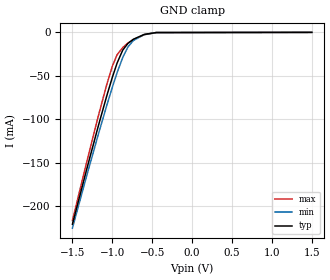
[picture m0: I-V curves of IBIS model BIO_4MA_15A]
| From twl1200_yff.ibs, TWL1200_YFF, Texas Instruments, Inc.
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[Model]   BIO_4MA_15A
Model_type  Input
Vinl=0.525
Vinh=0.975
| variable   typ   min   max
C_comp   2.92pF   2.50pF   3.51pF
[Temperature Range]   40   100   -40
| Ambient temperature   25   85   -40
[Voltage range]   1.5   1.4   1.6
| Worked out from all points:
|   GND clamp passes 1 mA (typ) near -0.53 V on its own axis
[GND Clamp]
| BIO_4MA_15A
|   Voltage   I(typ)   I(min)   I(max)
-1.5V     -220.4mA   -224.9mA   -216.2mA
-1.315V   -155.2mA   -162.8mA   -146.8mA
-1.175V   -107.4mA   -117.1mA   -96.01mA
-1.07V    -73.08mA   -84.08mA   -60.07mA
-1V       -51.72mA   -63.14mA   -38.92mA
-940mV    -35.29mA   -46.32mA   -25.69mA
-870mV    -20.5mA    -28.99mA   -17.51mA
-805mV    -12.74mA   -16.84mA   -12.3mA
-735mV    -7.856mA   -9.302mA   -8.241mA
-600mV    -2.372mA   -2.551mA   -2.677mA
-450mV    -245.3uA   -217.8uA   -153.4uA
1.5V      403.3pA    13.93nA    48.42pA
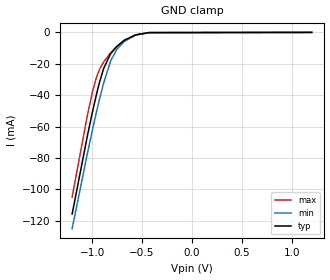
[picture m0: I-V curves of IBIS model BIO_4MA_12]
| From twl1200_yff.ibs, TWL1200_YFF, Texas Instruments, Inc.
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[Model]   BIO_4MA_12
Model_type  Input
Vinl=0.24
Vinh=0.96
| variable   typ   min   max
C_comp   2.96pF   2.58pF   3.55pF
[Temperature Range]   40   100   -40
| Ambient temperature   25   85   -40
[Voltage range]   1.2   1.1   1.3
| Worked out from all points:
|   GND clamp passes 1 mA (typ) near -0.53 V on its own axis
[GND Clamp]
| BIO_4MA_12
|   Voltage   I(typ)   I(min)   I(max)
-1.2V     -115.8mA   -125.1mA   -104.9mA
-1.045V   -65.27mA   -76.48mA   -52.1mA
-995mV    -50.27mA   -61.69mA   -37.59mA
-955mV    -39.16mA   -50.39mA   -28.36mA
-925mV    -31.62mA   -42.35mA   -23.44mA
-885mV    -23.11mA   -32.41mA   -18.91mA
-815mV    -13.64mA   -18.38mA   -13.02mA
-755mV    -9.083mA   -10.95mA   -9.266mA
-680mV    -5.018mA   -5.906mA   -5.701mA
-565mV    -1.615mA   -1.577mA   -1.685mA
-430mV    -157.4uA   -145uA     -87.99uA
1.2V      356.6pA    13.86nA    37.75pA
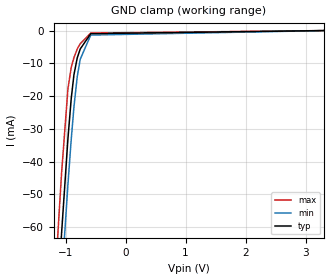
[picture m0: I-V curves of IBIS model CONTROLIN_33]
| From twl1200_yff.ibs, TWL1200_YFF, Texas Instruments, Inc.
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[Model]   CONTROLIN_33
Model_type  Input
Vinl=1.155
Vinh=2.145
| variable   typ   min   max
C_comp   1.78pF   1.41pF   2.49pF
[Temperature Range]   40   100   -40
| Ambient temperature   25   85   -40
[Voltage range]   3.3   3   3.6
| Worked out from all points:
|   GND clamp passes 1 mA (typ) near -0.58 V on its own axis
[GND Clamp]
| CONTROLIN_33
|   Voltage   I(typ)   I(min)   I(max)
-3.3V     -813.2mA   -810.9mA   -816.4mA
-1.18V    -96.35mA   -110.5mA   -78.5mA
-1.16V    -90.16mA   -104.4mA   -72.15mA
-1.11V    -74.91mA   -89.37mA   -56.61mA
-1.065V   -61.57mA   -76.14mA   -43.25mA
-960mV    -32.92mA   -46.91mA   -17.75mA
-905mV    -20.71mA   -33.14mA   -11.18mA
-860mV    -13.47mA   -23.31mA   -8.251mA
-805mV    -8.346mA   -14.02mA   -5.606mA
-755mV    -5.604mA   -8.734mA   -3.984mA
-580mV    -942uA     -1.365mA   -758.1uA
3.3V      193.8pA    963.2pA    46.32pA
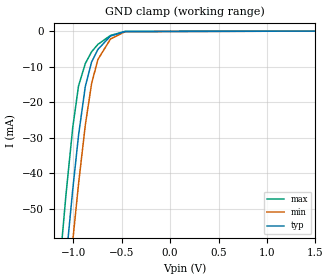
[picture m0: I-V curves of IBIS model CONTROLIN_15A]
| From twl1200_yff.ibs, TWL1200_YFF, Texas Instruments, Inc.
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[Model]   CONTROLIN_15A
Model_type  Input
Vinl=0.525
Vinh=0.975
| variable   typ   min   max
C_comp   1.95pF   1.64pF   2.47pF
[Temperature Range]   40   100   -40
| Ambient temperature   25   85   -40
[Voltage range]   1.5   1.4   1.6
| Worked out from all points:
|   GND clamp passes 1 mA (typ) near -0.58 V on its own axis
[GND Clamp]
| CONTROLIN_15A
|   Voltage   I(typ)   I(min)   I(max)
-1.5V     -199.5mA   -211.2mA   -185mA
-1.32V    -140.7mA   -153.9mA   -124.3mA
-1.18V    -96.35mA   -110.5mA   -78.5mA
-1.075V   -64.5mA    -79.05mA   -46.15mA
-1.005V   -44.62mA   -59.08mA   -27.16mA
-945mV    -29.31mA   -43.01mA   -15.42mA
-875mV    -15.55mA   -26.4mA    -9.12mA
-810mV    -8.688mA   -14.72mA   -5.81mA
-745mV    -5.153mA   -7.982mA   -3.732mA
-615mV    -1.388mA   -2.223mA   -1.219mA
-465mV    -156.2uA   -176.2uA   -62.84uA
1.5V      116.5pA    788.9pA    20.38pA
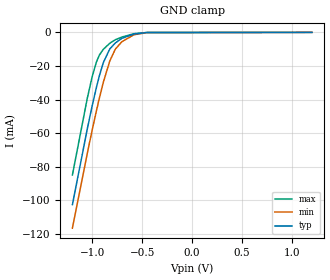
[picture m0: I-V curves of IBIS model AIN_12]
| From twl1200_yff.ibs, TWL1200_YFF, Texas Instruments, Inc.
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[Model]   AIN_12
Model_type  Input
Vinl=0.24
Vinh=0.96
| variable   typ   min   max
C_comp   2.13pF   1.79pF   2.63pF
[Temperature Range]   40   100   -40
| Ambient temperature   25   85   -40
[Voltage range]   1.2   1.1   1.3
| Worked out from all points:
|   GND clamp passes 1 mA (typ) near -0.59 V on its own axis
[GND Clamp]
| AIN_12
|   Voltage   I(typ)   I(min)   I(max)
-1.2V     -102.6mA   -116.6mA   -84.91mA
-1.05V    -57.23mA   -71.81mA   -38.99mA
-1V       -43.27mA   -57.7mA    -25.97mA
-960mV    -32.92mA   -46.91mA   -17.75mA
-930mV    -25.89mA   -39.21mA   -13.53mA
-890mV    -17.97mA   -29.69mA   -10.08mA
-825mV    -9.835mA   -16.99mA   -6.47mA
-770mV    -6.329mA   -10.03mA   -4.398mA
-705mV    -3.573mA   -5.62mA    -2.835mA
-585mV    -997.9uA   -1.471mA   -816.9uA
-455mV    -126.6uA   -144.1uA   -47.34uA
1.2V      105.6pA    761pA      16.3pA
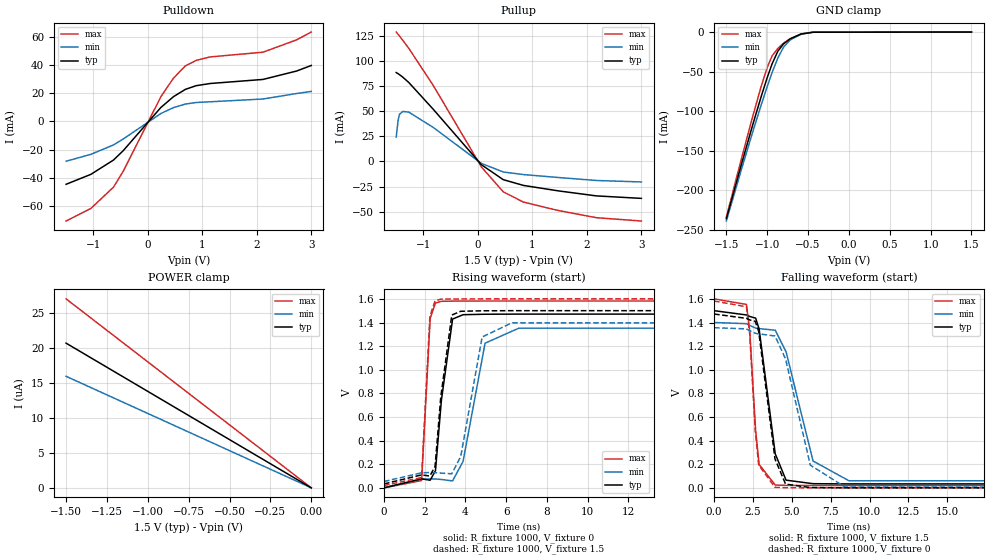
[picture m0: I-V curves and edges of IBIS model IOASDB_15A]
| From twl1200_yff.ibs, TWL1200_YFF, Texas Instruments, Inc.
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[Model]   IOASDB_15A
Model_type  I/O
Vinl=0.525
Vinh=0.975
Enable   Active-Low
Vref =   1.5
Rref =   1M
Cref =   15p
Vmeas =   0.75
| variable   typ   min   max
C_comp   4.28pF   3.66pF   5.02pF
| C_pullup   6.70pF   4.20pF   7.93pF
| C_pulldown   5.84pF   4.76pF   6.78pF
| C_tri-state   4.28pF   3.66pF   5.02pF
[Temperature Range]   40   100   -40
| Ambient temperature   25   85   -40
[Voltage range]   1.5   1.4   1.6
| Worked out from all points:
|   slope of the pulldown table from 0 to 0.225 V, typ, clamps not added: 24.1 ohm
|   slope of the pullup table from 0 to 0.225 V, typ, clamps not added: 21.7 ohm
|   GND clamp passes 1 mA (typ) near -0.51 V on its own axis
|   rising waveform, R_fixture 1000, V_fixture 0: 20-80 % time 399ps typ, 782ps min, 227ps max; typ from 0.001 V to 1.47 V
|   falling waveform, R_fixture 1000, V_fixture 1.5: 20-80 % time 796ps typ, 1.39ns min, 447ps max; typ from 1.5 V to 0.034 V
|   rising waveform, R_fixture 1000, V_fixture 1.5: 20-80 % time 388ps typ, 748ps min, 223ps max; typ from 0.034 V to 1.5 V
|   falling waveform, R_fixture 1000, V_fixture 0: 20-80 % time 779ps typ, 1.34ns min, 441ps max; typ from 1.47 V to 0.001 V
[GND Clamp]
| IOASDB_15A
|   Voltage   I(typ)   I(min)   I(max)
-1.5V     -235.9mA   -238.8mA   -234mA
-1.32V    -168.9mA   -175.3mA   -162mA
-1.18V    -118.3mA   -127.2mA   -107.7mA
-1.075V   -81.99mA   -92.53mA   -69.18mA
-1V       -57.7mA    -68.91mA   -44.76mA
-940mV    -40.23mA   -51.2mA    -30.27mA
-870mV    -24.29mA   -32.87mA   -20.72mA
-800mV    -15.03mA   -19.05mA   -14mA
-720mV    -8.614mA   -10.16mA   -8.634mA
-585mV    -2.51mA    -2.681mA   -2.42mA
-440mV    -273.1uA   -256.5uA   -157.3uA
1.5V      381.3pA    1.072uA    -1.806uA
[POWER Clamp]
| IOASDB_15A
|   Voltage   I(typ)   I(min)   I(max)
-1.5V     20.74uA    15.99uA    27.09uA
-245mV    3.388uA    2.615uA    4.425uA
-55mV     763.2nA    594.2nA    995nA
0V        0A         0A         0A
[Pulldown]
| IOASDB_15A
|   Voltage   I(typ)   I(min)   I(max)
-1.5V     -44.54mA   -28.21mA   -70.53mA
-1.045V   -37.49mA   -23.32mA   -61.63mA
-630mV    -27.36mA   -16.66mA   -46.56mA
-455mV    -20.89mA   -12.56mA   -35.58mA
240mV     9.862mA    5.599mA    17.46mA
470mV     17.47mA    9.763mA    30.59mA
690mV     22.69mA    12.27mA    39.3mA
885mV     25.26mA    13.37mA    43.14mA
1.145V    26.84mA    13.88mA    45.66mA
2.115V    29.72mA    15.87mA    49mA
2.73V     35.65mA    19.74mA    57.72mA
3V        39.59mA    21.22mA    63.28mA
[Pullup]
| IOASDB_15A
|   Voltage   I(typ)   I(min)   I(max)
-1.5V     88.68mA    24.39mA    129.1mA
-1.465V   87.52mA    40.98mA    126.8mA
-1.44V    86.59mA    47.09mA    125.1mA
-1.38V    84.11mA    49.88mA    120.9mA
-1.27V    78.82mA    49.25mA    112.9mA
-820mV    52.04mA    33.94mA    75.81mA
65mV      -3.308mA   -1.988mA   -5.569mA
465mV     -18.16mA   -10.5mA    -30.28mA
835mV     -23.89mA   -13.07mA   -40.53mA
1.475V    -29.33mA   -15.99mA   -48.93mA
2.175V    -34.35mA   -18.98mA   -56.1mA
3V        -36.82mA   -20.43mA   -59.4mA
[Ramp]
| IOASDB_15A
| variable   typ   min   max
dV/dt_r   0.88/4.07E-10   0.81/7.87E-10   0.95/2.38E-10
dV/dt_f   0.88/7.95E-10   0.81/1.39E-09   0.95/4.52E-10
R_load = 1000
[Rising Waveform]
| IOASDB_15A
R_fixture =   1000
C_fixture =   0
L_fixture =   0
V_fixture =   0
V_fixture_min = 0
V_fixture_max = 0
|   Time   V(typ)   V(min)   V(max)
0s        1.219mV    1.392mV    1.097mV
1.85ns    77.19mV    74.27mV    62.74mV
2.27ns    65.68mV    76.72mV    1.435V
2.53ns    146.6mV    76.32mV    1.565V
2.82ns    741.4mV    72mV       1.579V
3.37ns    1.429V     59.84mV    1.581V
3.885ns   1.466V     225.1mV    1.581V
4.965ns   1.47V      1.225V     1.582V
6.62ns    1.471V     1.352V     1.582V
239.8ns   1.472V     1.356V     1.582V
[Falling Waveform]
| IOASDB_15A
R_fixture =   1000
C_fixture =   0
L_fixture =   0
V_fixture =   1.5
V_fixture_min = 1.4
V_fixture_max = 1.6
|   Time   V(typ)   V(min)   V(max)
0s        1.5V       1.4V       1.6V
2.08ns    1.464V     1.39V      1.553V
2.295ns   1.451V     1.375V     1.328V
2.675ns   1.437V     1.353V     482.3mV
2.9ns     1.344V     1.348V     199mV
3.935ns   289.1mV    1.335V     24.75mV
4.63ns    66.26mV    1.153V     21.91mV
6.365ns   36.28mV    228.6mV    20.97mV
8.675ns   34.4mV     61.07mV    20.9mV
239.8ns   34.24mV    54.66mV    20.9mV
[Rising Waveform]
| IOASDB_15A
R_fixture =   1000
C_fixture =   0
L_fixture =   0
V_fixture =   1.5
V_fixture_min = 1.4
V_fixture_max = 1.6
|   Time   V(typ)   V(min)   V(max)
0s        34.24mV    54.66mV    20.9mV
1.85ns    110.8mV    128.5mV    88.5mV
2.255ns   101.1mV    130.6mV    1.451V
2.51ns    182.9mV    129.9mV    1.584V
2.79ns    769.7mV    125.6mV    1.597V
3.33ns    1.463V     120.2mV    1.599V
3.77ns    1.495V     266.4mV    1.599V
4.82ns    1.499V     1.277V     1.6V
6.28ns    1.5V       1.397V     1.6V
239.8ns   1.5V       1.4V       1.6V
[Falling Waveform]
| IOASDB_15A
R_fixture =   1000
C_fixture =   0
L_fixture =   0
V_fixture =   0
V_fixture_min = 0
V_fixture_max = 0
|   Time   V(typ)   V(min)   V(max)
0s        1.472V     1.356V     1.582V
2.08ns    1.435V     1.346V     1.533V
2.29ns    1.422V     1.331V     1.309V
2.645ns   1.41V      1.309V     494.1mV
2.87ns    1.326V     1.304V     194.5mV
3.92ns    245.4mV    1.286V     4.916mV
4.6ns     32.89mV    1.091V     2.113mV
6.195ns   3.528mV    192.9mV    1.183mV
8.43ns    1.408mV    7.782mV    1.102mV
239.8ns   1.219mV    1.392mV    1.097mV
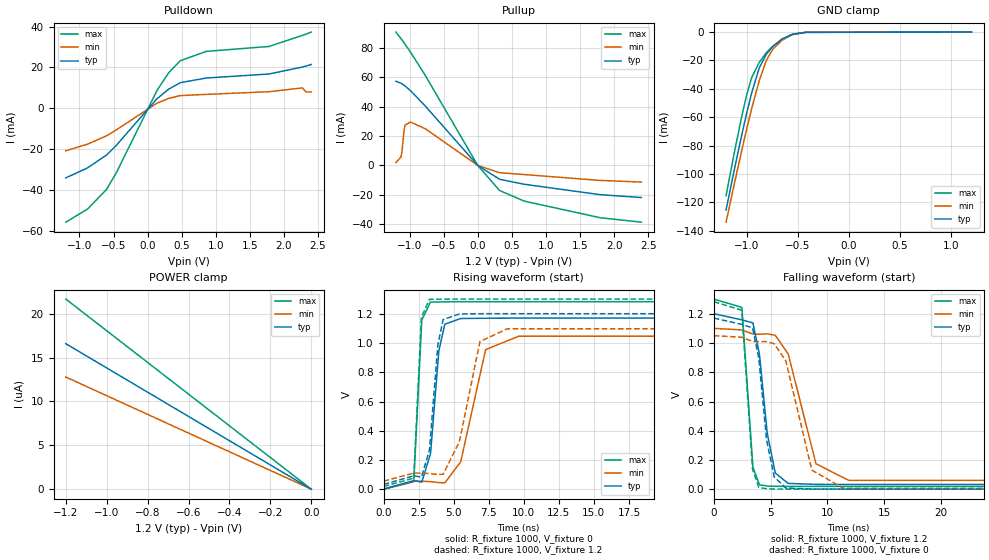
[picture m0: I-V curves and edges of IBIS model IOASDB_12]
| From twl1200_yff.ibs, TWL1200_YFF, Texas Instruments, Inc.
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[Model]   IOASDB_12
Model_type  I/O
Vinl=0.24
Vinh=0.96
Enable   Active-Low
Vref =   1.2
Rref =   1M
Cref =   15p
Vmeas =   0.6
| variable   typ   min   max
C_comp   4.36pF   3.78pF   5.03pF
| C_pullup   6.71pF   4.15pF   7.79pF
| C_pulldown   5.97pF   4.66pF   7.07pF
| C_tri-state   4.36pF   3.78pF   5.03pF
[Temperature Range]   40   100   -40
| Ambient temperature   25   85   -40
[Voltage range]   1.2   1.1   1.3
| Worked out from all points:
|   slope of the pulldown table from 0 to 0.18 V, typ, clamps not added: 30 ohm
|   slope of the pullup table from 0 to 0.18 V, typ, clamps not added: 29.5 ohm
|   GND clamp passes 1 mA (typ) near -0.51 V on its own axis
|   rising waveform, R_fixture 1000, V_fixture 0: 20-80 % time 593ps typ, 1.32ns min, 296ps max; typ from 0.001 V to 1.17 V
|   falling waveform, R_fixture 1000, V_fixture 1.2: 20-80 % time 967ps typ, 1.8ns min, 526ps max; typ from 1.2 V to 0.033 V
|   rising waveform, R_fixture 1000, V_fixture 1.2: 20-80 % time 579ps typ, 1.3ns min, 291ps max; typ from 0.033 V to 1.2 V
|   falling waveform, R_fixture 1000, V_fixture 0: 20-80 % time 938ps typ, 1.71ns min, 516ps max; typ from 1.17 V to 0.001 V
[GND Clamp]
| IOASDB_12
|   Voltage   I(typ)   I(min)   I(max)
-1.2V     -125.4mA   -134mA     -115.3mA
-1.115V   -95.58mA   -105.6mA   -83.48mA
-1.045V   -72.04mA   -82.92mA   -58.91mA
-995mV    -56.16mA   -67.38mA   -43.31mA
-950mV    -42.96mA   -54.05mA   -32.2mA
-875mV    -25.19mA   -34.06mA   -21.26mA
-805mV    -15.51mA   -19.83mA   -14.41mA
-745mV    -10.38mA   -12.31mA   -10.11mA
-655mV    -4.945mA   -5.886mA   -5.237mA
-550mV    -1.666mA   -1.631mA   -1.426mA
-420mV    -178.9uA   -173.3uA   -100.4uA
1.2V      343.5pA    1.071uA    -1.806uA
[POWER Clamp]
| IOASDB_12
|   Voltage   I(typ)   I(min)   I(max)
-1.2V     16.59uA    12.79uA    21.68uA
-235mV    3.25uA     2.509uA    4.245uA
-55mV     762.8nA    593.8nA    994.6nA
0V        0A         0A         0A
[Pulldown]
| IOASDB_12
|   Voltage   I(typ)   I(min)   I(max)
-1.2V     -34.16mA   -20.86mA   -55.9mA
-880mV    -29.25mA   -17.59mA   -49.43mA
-600mV    -22.87mA   -13.51mA   -39.73mA
-455mV    -18.06mA   -10.53mA   -31.39mA
135mV     4.595mA    2.44mA     8.564mA
310mV     9.394mA    4.847mA    17.44mA
480mV     12.56mA    6.196mA    23.32mA
860mV     14.82mA    6.8mA      27.89mA
1.78V     16.8mA     8.109mA    30.31mA
2.27V     20.2mA     9.988mA    35.76mA
2.325V    20.72mA    7.982mA    36.37mA
2.4V      21.47mA    8.028mA    37.36mA
[Pullup]
| IOASDB_12
|   Voltage   I(typ)   I(min)   I(max)
-1.2V     57.23mA    1.913mA    90.66mA
-1.125V   55.86mA    5.779mA    86.17mA
-1.11V    55.43mA    9.937mA    85.23mA
-1.08V    54.48mA    24.08mA    83.32mA
-1.065V   53.96mA    27.55mA    82.34mA
-985mV    50.81mA    29.49mA    76.97mA
-770mV    40.38mA    24.95mA    61.25mA
0V        0A         0A         0A
320mV     -9.412mA   -4.959mA   -17.06mA
680mV     -12.81mA   -6.201mA   -24.25mA
1.795V    -19.89mA   -10.21mA   -35.57mA
2.4V      -21.85mA   -11.32mA   -38.61mA
[Ramp]
| IOASDB_12
| variable   typ   min   max
dV/dt_r   0.70/5.99E-10   0.63/1.32E-09   0.77/3.05E-10
dV/dt_f   0.70/9.68E-10   0.63/1.80E-09   0.77/5.32E-10
R_load = 1000
[Rising Waveform]
| IOASDB_12
R_fixture =   1000
C_fixture =   0
L_fixture =   0
V_fixture =   0
V_fixture_min = 0
V_fixture_max = 0
|   Time   V(typ)   V(min)   V(max)
0s        1.175mV    1.391mV    1.032mV
2.15ns    59.8mV     55.59mV    52.23mV
2.72ns    49.51mV    54.95mV    1.157V
3.345ns   243.7mV    52.59mV    1.279V
3.94ns    947.1mV    45.91mV    1.28V
4.36ns    1.128V     43.73mV    1.281V
5.495ns   1.167V     187.3mV    1.282V
7.275ns   1.169V     954.4mV    1.282V
9.63ns    1.17V      1.046V     1.282V
239.8ns   1.17V      1.05V      1.282V
[Falling Waveform]
| IOASDB_12
R_fixture =   1000
C_fixture =   0
L_fixture =   0
V_fixture =   1.2
V_fixture_min = 1.1
V_fixture_max = 1.3
|   Time   V(typ)   V(min)   V(max)
0s        1.2V       1.1V       1.3V
2.47ns    1.158V     1.089V     1.243V
3.44ns    1.137V     1.061V     152mV
4.02ns    921mV      1.06V      30.29mV
4.695ns   385.9mV    1.062V     22.66mV
5.41ns    111.2mV    1.053V     20.68mV
6.545ns   40.19mV    924.9mV    19.91mV
8.99ns    34.02mV    174.2mV    19.78mV
11.87ns   33.39mV    61.36mV    19.78mV
239.8ns   33.35mV    55.73mV    19.78mV
[Rising Waveform]
| IOASDB_12
R_fixture =   1000
C_fixture =   0
L_fixture =   0
V_fixture =   1.2
V_fixture_min = 1.1
V_fixture_max = 1.3
|   Time   V(typ)   V(min)   V(max)
0s        33.35mV    55.73mV    19.78mV
2.145ns   92.58mV    111mV      76.36mV
2.695ns   83.34mV    110.7mV    1.175V
3.265ns   266.4mV    107.6mV    1.298V
3.865ns   986.1mV    101.1mV    1.299V
4.24ns    1.16V      102.6mV    1.299V
5.4ns     1.198V     323.3mV    1.3V
6.87ns    1.2V       1.01V      1.3V
8.82ns    1.2V       1.097V     1.3V
239.8ns   1.2V       1.1V       1.3V
[Falling Waveform]
| IOASDB_12
R_fixture =   1000
C_fixture =   0
L_fixture =   0
V_fixture =   0
V_fixture_min = 0
V_fixture_max = 0
|   Time   V(typ)   V(min)   V(max)
0s        1.17V      1.05V      1.282V
2.46ns    1.127V     1.039V     1.224V
3.41ns    1.103V     1.01V      138.5mV
3.955ns   898.5mV    1.009V     12.59mV
4.64ns    339.4mV    1.009V     3.983mV
5.315ns   84.59mV    994.8mV    2.032mV
6.335ns   8.878mV    877.6mV    1.205mV
8.62ns    2.01mV     131.3mV    1.038mV
11.41ns   1.228mV    6.555mV    1.032mV
239.8ns   1.175mV    1.391mV    1.032mV
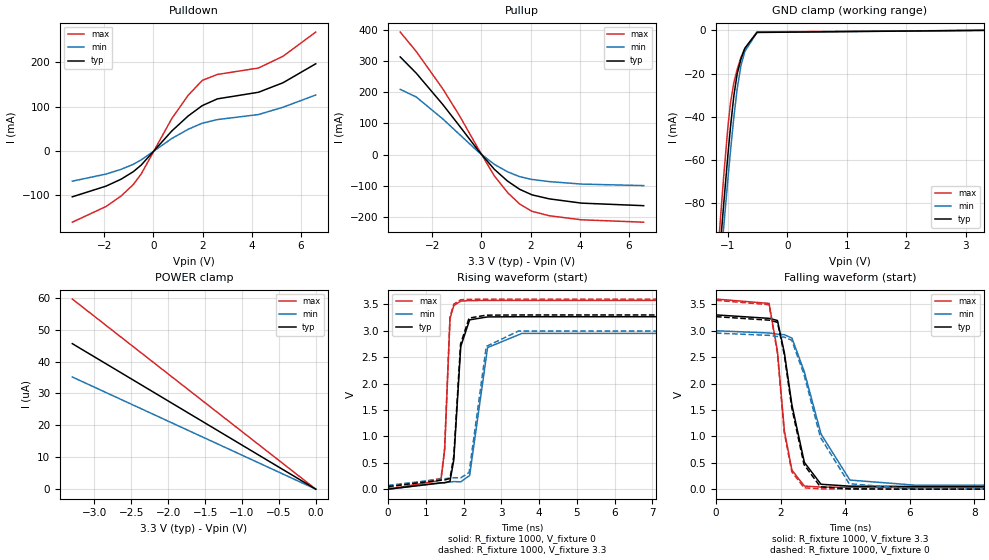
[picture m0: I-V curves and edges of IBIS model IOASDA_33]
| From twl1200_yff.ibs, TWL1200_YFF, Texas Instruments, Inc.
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[Model]   IOASDA_33
Model_type  I/O
Vinl=1.155
Vinh=2.145
Enable   Active-Low
Vref =   3.3
Rref =   1M
Cref =   15p
Vmeas =   1.65
| variable   typ   min   max
C_comp   3.94pF   3.25pF   4.99pF
| C_pullup   5.97pF   3.66pF   7.48pF
| C_pulldown   5.12pF   4.47pF   6.03pF
| C_tri-state   3.94pF   3.25pF   4.99pF
[Temperature Range]   40   100   -40
| Ambient temperature   25   85   -40
[Voltage range]   3.3   3   3.6
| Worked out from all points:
|   slope of the pulldown table from 0 to 0.495 V, typ, clamps not added: 16 ohm
|   slope of the pullup table from 0 to 0.495 V, typ, clamps not added: 11 ohm
|   GND clamp passes 1 mA (typ) near -0.51 V on its own axis
|   rising waveform, R_fixture 1000, V_fixture 0: 20-80 % time 161ps typ, 261ps min, 102ps max; typ from 0.002 V to 3.27 V
|   falling waveform, R_fixture 1000, V_fixture 3.3: 20-80 % time 537ps typ, 860ps min, 347ps max; typ from 3.3 V to 0.052 V
|   rising waveform, R_fixture 1000, V_fixture 3.3: 20-80 % time 157ps typ, 252ps min, 100ps max; typ from 0.052 V to 3.3 V
|   falling waveform, R_fixture 1000, V_fixture 0: 20-80 % time 532ps typ, 847ps min, 345ps max; typ from 3.27 V to 0.002 V
[GND Clamp]
| IOASDA_33
|   Voltage   I(typ)   I(min)   I(max)
-3.3V     -943.8mA   -910.6mA   -986.7mA
-1.135V   -102.5mA   -112.2mA   -90.87mA
-1.1V     -90.48mA   -100.7mA   -78.1mA
-1.07V    -80.34mA   -90.94mA   -67.48mA
-1V       -57.74mA   -68.94mA   -44.8mA
-955mV    -44.39mA   -55.52mA   -33.29mA
-900mV    -30.36mA   -40.35mA   -24.25mA
-845mV    -20.31mA   -27.31mA   -18.16mA
-780mV    -13.22mA   -16.23mA   -12.49mA
-715mV    -8.31mA    -9.796mA   -8.393mA
-510mV    -983.4uA   -892.8uA   -733.4uA
3.3V      659.2pA    3.202uA    -5.419uA
[POWER Clamp]
| IOASDA_33
|   Voltage   I(typ)   I(min)   I(max)
-3.3V     45.63uA    35.17uA    59.61uA
-1.805V   24.96uA    19.24uA    32.6uA
-1.72V    23.78uA    18.33uA    31.07uA
-1.34V    18.53uA    14.29uA    24.2uA
-1.025V   14.17uA    10.93uA    18.51uA
0V        0A         0A         0A
[Pulldown]
| IOASDA_33
|   Voltage   I(typ)   I(min)   I(max)
-3.3V     -103.3mA   -68mA      -160.6mA
-1.925V   -79.15mA   -51.92mA   -125.1mA
-1.315V   -63.52mA   -41.37mA   -101.4mA
-820mV    -46.62mA   -29.98mA   -75.65mA
-495mV    -31.49mA   -19.98mA   -51.46mA
745mV     45.19mA    28.24mA    73.22mA
1.415V    79.25mA    49.15mA    126mA
1.985V    102.5mA    62.8mA     159.4mA
2.6V      117.7mA    70.95mA    172.8mA
4.27V     132.6mA    82.34mA    187.3mA
5.27V     154.1mA    98.81mA    213.9mA
6.6V      196.9mA    126.4mA    268.4mA
[Pullup]
| IOASDA_33
|   Voltage   I(typ)   I(min)   I(max)
-3.3V     314.4mA    209.9mA    394.5mA
-2.65V    262.2mA    185.4mA    332.2mA
-1.565V   160.7mA    114.4mA    211.1mA
-890mV    92.03mA    64.72mA    125.1mA
-115mV    11.64mA    7.916mA    16.83mA
525mV     -47.51mA   -31.59mA   -68.58mA
1.06V     -85.35mA   -55.6mA    -122.2mA
1.555V    -112.1mA   -71.37mA   -159.5mA
2.06V     -130mA     -80.43mA   -183.1mA
2.76V     -142.9mA   -87.23mA   -197.3mA
4.075V    -156.7mA   -95.34mA   -210.4mA
6.6V      -164.9mA   -100.2mA   -218.1mA
[Ramp]
| IOASDA_33
| variable   typ   min   max
dV/dt_r   1.96/1.69E-10   1.77/2.73E-10   2.14/1.04E-10
dV/dt_f   1.95/5.40E-10   1.76/8.62E-10   2.14/3.48E-10
R_load = 1000
[Rising Waveform]
| IOASDA_33
R_fixture =   1000
C_fixture =   0
L_fixture =   0
V_fixture =   0
V_fixture_min = 0
V_fixture_max = 0
|   Time   V(typ)   V(min)   V(max)
0s        1.876mV    1.928mV    1.86mV
1.4ns     122.1mV    117.4mV    169.6mV
1.5ns     123.8mV    125.6mV    764.2mV
1.64ns    151.1mV    137.3mV    3.231V
1.74ns    554.2mV    145.6mV    3.476V
1.925ns   2.705V     141.1mV    3.562V
2.16ns    3.207V     261.3mV    3.571V
2.635ns   3.262V     2.682V     3.574V
3.545ns   3.266V     2.95V      3.575V
239.8ns   3.267V     2.956V     3.576V
[Falling Waveform]
| IOASDA_33
R_fixture =   1000
C_fixture =   0
L_fixture =   0
V_fixture =   3.3
V_fixture_min = 3
V_fixture_max = 3.6
|   Time   V(typ)   V(min)   V(max)
0s        3.3V       3V         3.6V
1.645ns   3.235V     2.958V     3.518V
1.905ns   3.194V     2.936V     2.615V
2.12ns    2.582V     2.925V     1.105V
2.355ns   1.592V     2.861V     360.3mV
2.74ns    507.9mV    2.221V     60.81mV
3.255ns   94.49mV    1.047V     41.25mV
4.15ns    58.62mV    174mV      36.18mV
6.16ns    52.64mV    78.21mV    35.18mV
239.8ns   52.07mV    74.22mV    35.12mV
[Rising Waveform]
| IOASDA_33
R_fixture =   1000
C_fixture =   0
L_fixture =   0
V_fixture =   3.3
V_fixture_min = 3
V_fixture_max = 3.6
|   Time   V(typ)   V(min)   V(max)
0s        52.07mV    74.22mV    35.12mV
1.4ns     173.2mV    191mV      205.2mV
1.495ns   175.4mV    198.9mV    743.7mV
1.64ns    204.8mV    210.9mV    3.264V
1.74ns    624.7mV    219.1mV    3.504V
1.92ns    2.751V     215.3mV    3.587V
2.145ns   3.24V      316.6mV    3.595V
2.6ns     3.295V     2.703V     3.598V
3.45ns    3.299V     2.994V     3.599V
239.8ns   3.3V       3V         3.6V
[Falling Waveform]
| IOASDA_33
R_fixture =   1000
C_fixture =   0
L_fixture =   0
V_fixture =   0
V_fixture_min = 0
V_fixture_max = 0
|   Time   V(typ)   V(min)   V(max)
0s        3.267V     2.956V     3.576V
1.645ns   3.201V     2.913V     3.493V
1.905ns   3.16V      2.891V     2.574V
2.115ns   2.555V     2.881V     1.078V
2.35ns    1.541V     2.818V     331.7mV
2.73ns    465.9mV    2.172V     28.08mV
3.235ns   47.33mV    986mV      8.157mV
4.13ns    8.492mV    104.7mV    2.935mV
6.12ns    2.465mV    5.944mV    1.918mV
239.8ns   1.877mV    1.929mV    1.86mV
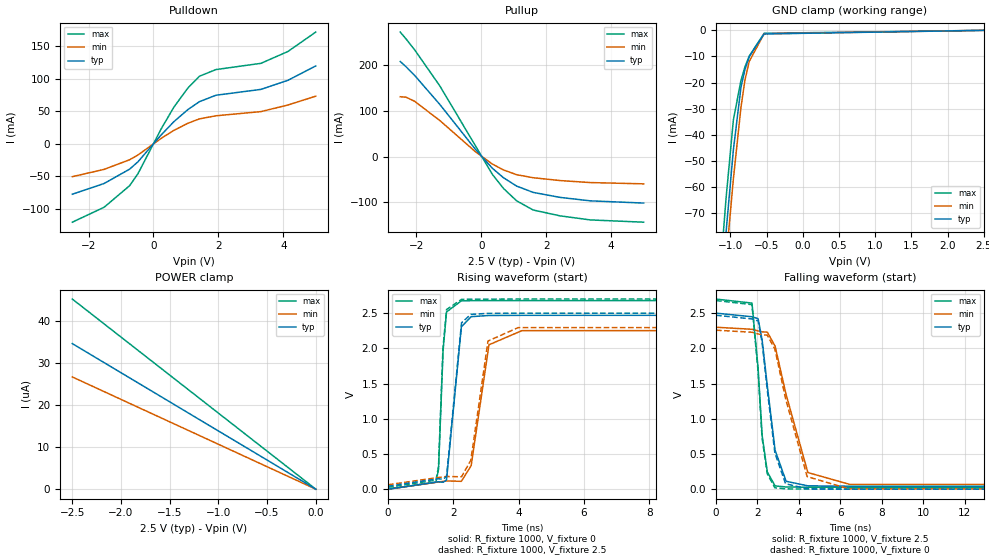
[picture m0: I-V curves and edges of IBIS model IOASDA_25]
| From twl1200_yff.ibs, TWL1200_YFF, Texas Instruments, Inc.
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[Model]   IOASDA_25
Model_type  I/O
Vinl=0.875
Vinh=1.625
Enable   Active-Low
Vref =   2.5
Rref =   1M
Cref =   15p
Vmeas =   1.25
| variable   typ   min   max
C_comp   4.06pF   3.38pF   4.99pF
| C_pullup   6.32pF   3.84pF   7.75pF
| C_pulldown   5.38pF   4.61pF   6.25pF
| C_tri-state   4.06pF   3.38pF   4.99pF
[Temperature Range]   40   100   -40
| Ambient temperature   25   85   -40
[Voltage range]   2.5   2.3   2.7
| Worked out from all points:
|   slope of the pulldown table from 0 to 0.375 V, typ, clamps not added: 17.8 ohm
|   slope of the pullup table from 0 to 0.375 V, typ, clamps not added: 13.2 ohm
|   GND clamp passes 1 mA (typ) near -0.51 V on its own axis
|   rising waveform, R_fixture 1000, V_fixture 0: 20-80 % time 216ps typ, 361ps min, 132ps max; typ from 0.002 V to 2.47 V
|   falling waveform, R_fixture 1000, V_fixture 2.5: 20-80 % time 590ps typ, 970ps min, 365ps max; typ from 2.5 V to 0.043 V
|   rising waveform, R_fixture 1000, V_fixture 2.5: 20-80 % time 212ps typ, 346ps min, 129ps max; typ from 0.043 V to 2.5 V
|   falling waveform, R_fixture 1000, V_fixture 0: 20-80 % time 583ps typ, 952ps min, 361ps max; typ from 2.47 V to 0.002 V
[GND Clamp]
| IOASDA_25
|   Voltage   I(typ)   I(min)   I(max)
-2.5V     -624.7mA   -607.3mA   -648.7mA
-1.145V   -106mA     -115.5mA   -94.56mA
-1.13V    -100.8mA   -110.5mA   -89.01mA
-1.1V     -90.46mA   -100.7mA   -78.08mA
-1.075V   -82.01mA   -92.54mA   -69.21mA
-1.06V    -77mA      -87.72mA   -64.01mA
-960mV    -45.8mA    -56.97mA   -34.37mA
-855mV    -21.79mA   -29.46mA   -19.15mA
-800mV    -15.04mA   -19.06mA   -14.02mA
-740mV    -10.03mA   -11.86mA   -9.831mA
-535mV    -1.389mA   -1.312mA   -1.131mA
2.5V      522.9pA    2.136uA    -3.613uA
[POWER Clamp]
| IOASDA_25
|   Voltage   I(typ)   I(min)   I(max)
-2.5V     34.57uA    26.65uA    45.15uA
-90mV     1.247uA    966.3nA    1.634uA
-60mV     834.2nA    648.8nA    1.087uA
0V        0A         0A         0A
[Pulldown]
| IOASDA_25
|   Voltage   I(typ)   I(min)   I(max)
-2.5V     -77.88mA   -50.81mA   -121mA
-1.52V    -61.28mA   -39.53mA   -97.94mA
-735mV    -39.17mA   -24.7mA    -64.71mA
-480mV    -27.99mA   -17.43mA   -46.42mA
240mV     13.73mA    8.364mA    23.09mA
630mV     34.06mA    20.63mA    56.53mA
1.06V     52.64mA    31.56mA    85.91mA
1.415V    64.85mA    38.32mA    104.1mA
1.925V    74.79mA    43.12mA    114.4mA
3.31V     83.83mA    49.55mA    124mA
4.14V     97.75mA    59.7mA     142.2mA
5V        120mA      73.35mA    172.2mA
[Pullup]
| IOASDA_25
|   Voltage   I(typ)   I(min)   I(max)
-2.5V     208.7mA    131.3mA    273.3mA
-2.32V    197.1mA    130.3mA    258.2mA
-2.055V   178mA      121.2mA    234.2mA
-1.275V   113.9mA    78.72mA    154.5mA
-185mV    15.92mA    10.55mA    23.74mA
335mV     -25.63mA   -16.46mA   -38.91mA
680mV     -46.63mA   -29.48mA   -70.1mA
1.085V    -64.95mA   -39.96mA   -97.35mA
1.595V    -78.85mA   -46.61mA   -117.5mA
2.425V    -89.81mA   -52.86mA   -130.4mA
3.355V    -97.41mA   -57.27mA   -139.3mA
5V        -102.3mA   -60.07mA   -144.3mA
[Ramp]
| IOASDA_25
| variable   typ   min   max
dV/dt_r   1.48/2.23E-10   1.35/3.68E-10   1.61/1.44E-10
dV/dt_f   1.47/5.92E-10   1.34/9.72E-10   1.60/3.68E-10
R_load = 1000
[Rising Waveform]
| IOASDA_25
R_fixture =   1000
C_fixture =   0
L_fixture =   0
V_fixture =   0
V_fixture_min = 0
V_fixture_max = 0
|   Time   V(typ)   V(min)   V(max)
0s        1.554mV    1.656mV    1.491mV
1.465ns   101.6mV    98.71mV    99.57mV
1.545ns   106.9mV    103.6mV    282.8mV
1.685ns   99.57mV    112mV      1.974V
1.79ns    131.1mV    118.3mV    2.517V
2.245ns   2.306V     112.5mV    2.675V
2.545ns   2.45V      335.7mV    2.677V
3.09ns    2.467V     2.051V     2.678V
4.1ns     2.469V     2.252V     2.679V
239.8ns   2.47V      2.258V     2.679V
[Falling Waveform]
| IOASDA_25
R_fixture =   1000
C_fixture =   0
L_fixture =   0
V_fixture =   2.5
V_fixture_min = 2.3
V_fixture_max = 2.7
|   Time   V(typ)   V(min)   V(max)
0s        2.5V       2.3V       2.7V
1.735ns   2.449V     2.271V     2.643V
2.03ns    2.422V     2.248V     1.719V
2.225ns   2.118V     2.235V     764.3mV
2.475ns   1.468V     2.231V     245.5mV
2.85ns    554.3mV    2.032V     47.75mV
3.38ns    113.4mV    1.345V     32.7mV
4.43ns    48.46mV    237.2mV    28.85mV
6.455ns   43.68mV    68.86mV    28.25mV
239.8ns   43.23mV    63.98mV    28.21mV
[Rising Waveform]
| IOASDA_25
R_fixture =   1000
C_fixture =   0
L_fixture =   0
V_fixture =   2.5
V_fixture_min = 2.3
V_fixture_max = 2.7
|   Time   V(typ)   V(min)   V(max)
0s        43.23mV    63.98mV    28.21mV
1.465ns   144.2mV    162.4mV    128.5mV
1.545ns   149.4mV    167.3mV    318.6mV
1.68ns    143.2mV    175.4mV    1.994V
1.79ns    178.2mV    181.9mV    2.551V
2.25ns    2.363V     177.2mV    2.696V
2.535ns   2.483V     412.6mV    2.698V
3.06ns    2.497V     2.104V     2.699V
3.985ns   2.499V     2.295V     2.7V
239.8ns   2.5V       2.3V       2.7V
[Falling Waveform]
| IOASDA_25
R_fixture =   1000
C_fixture =   0
L_fixture =   0
V_fixture =   0
V_fixture_min = 0
V_fixture_max = 0
|   Time   V(typ)   V(min)   V(max)
0s        2.47V      2.258V     2.679V
1.735ns   2.418V     2.229V     2.621V
2.03ns    2.39V      2.205V     1.673V
2.22ns    2.091V     2.193V     736.6mV
2.47ns    1.417V     2.188V     220.6mV
2.84ns    513.6mV    1.99V      21.07mV
3.355ns   77.85mV    1.288V     6.124mV
4.395ns   6.908mV    179.8mV    2.152mV
6.4ns     2.019mV    6.51mV     1.533mV
239.8ns   1.554mV    1.656mV    1.491mV
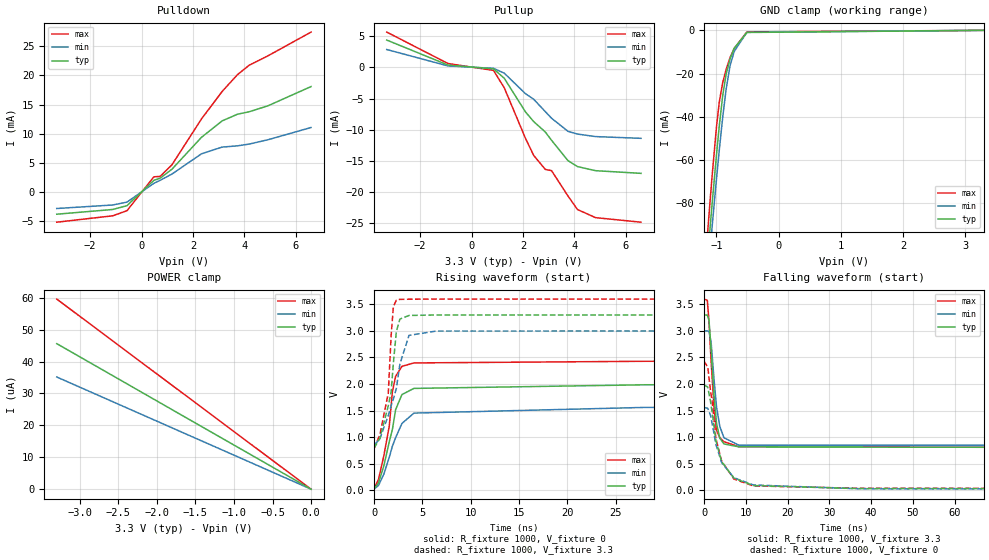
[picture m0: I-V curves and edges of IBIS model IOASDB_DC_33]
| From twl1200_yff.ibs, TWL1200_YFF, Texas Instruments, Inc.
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[Model]   IOASDB_DC_33
Model_type  I/O
Vinl=1.155
Vinh=2.145
Enable   Active-Low
Vref =   3.3
Rref =   1M
Cref =   15p
Vmeas =   1.65
| variable   typ   min   max
C_comp   3.94pF   3.25pF   4.99pF
| C_pullup   3.93pF   3.25pF   4.96pF
| C_pulldown   4.23pF   3.38pF   5.23pF
| C_tri-state   3.94pF   3.25pF   4.99pF
[Temperature Range]   40   100   -40
| Ambient temperature   25   85   -40
[Voltage range]   3.3   3   3.6
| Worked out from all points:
|   slope of the pulldown table from 0 to 0.495 V, typ, clamps not added: 233 ohm
|   slope of the pullup table from 0 to 0.495 V, typ, clamps not added: 4.25 kohm
|   GND clamp passes 1 mA (typ) near -0.51 V on its own axis
|   rising waveform, R_fixture 1000, V_fixture 0: 20-80 % time 1.38ns typ, 1.8ns min, 1.11ns max; typ from 0.023 V to 1.99 V
|   falling waveform, R_fixture 1000, V_fixture 3.3: 20-80 % time 1.36ns typ, 1.63ns min, 1.32ns max; typ from 3.3 V to 0.79 V
|   rising waveform, R_fixture 1000, V_fixture 3.3: 20-80 % time 1.09ns typ, 1.61ns min, 830ps max; typ from 0.79 V to 3.3 V
|   falling waveform, R_fixture 1000, V_fixture 0: 20-80 % time 3.32ns typ, 3.86ns min, 2.97ns max; typ from 1.99 V to 0.024 V
[GND Clamp]
| IOASDB_DC_33
|   Voltage   I(typ)   I(min)   I(max)
-3.3V     -943.8mA   -910.6mA   -986.7mA
-1.135V   -102.5mA   -112.2mA   -90.87mA
-1.1V     -90.48mA   -100.7mA   -78.1mA
-1.07V    -80.34mA   -90.94mA   -67.48mA
-1V       -57.74mA   -68.94mA   -44.8mA
-955mV    -44.39mA   -55.52mA   -33.29mA
-900mV    -30.36mA   -40.35mA   -24.25mA
-845mV    -20.31mA   -27.31mA   -18.16mA
-780mV    -13.22mA   -16.23mA   -12.49mA
-715mV    -8.31mA    -9.796mA   -8.393mA
-510mV    -983.4uA   -892.8uA   -733.4uA
3.3V      659.2pA    3.202uA    -5.419uA
[POWER Clamp]
| IOASDB_DC_33
|   Voltage   I(typ)   I(min)   I(max)
-3.3V     45.63uA    35.17uA    59.61uA
-1.805V   24.96uA    19.24uA    32.6uA
-1.72V    23.78uA    18.33uA    31.07uA
-1.34V    18.53uA    14.29uA    24.2uA
-1.025V   14.17uA    10.93uA    18.51uA
0V        0A         0A         0A
[Pulldown]
| IOASDB_DC_33
|   Voltage   I(typ)   I(min)   I(max)
-3.3V     -3.819mA   -2.841mA   -5.19mA
-1.12V    -3.008mA   -2.239mA   -4.094mA
-565mV    -2.354mA   -1.744mA   -3.214mA
480mV     1.992mA    1.479mA    2.596mA
725mV     2.365mA    1.996mA    2.673mA
1.185V    3.904mA    3.071mA    4.661mA
2.335V    9.378mA    6.547mA    12.53mA
3.14V     12.2mA     7.701mA    17.25mA
3.735V    13.34mA    7.914mA    20.13mA
4.195V    13.77mA    8.219mA    21.76mA
4.925V    14.79mA    8.967mA    23.37mA
6.6V      18.09mA    11.06mA    27.44mA
[Pullup]
| IOASDB_DC_33
|   Voltage   I(typ)   I(min)   I(max)
-3.3V     4.399mA    2.88mA     5.68mA
-915mV    378.9uA    237.3uA    624uA
855mV     -230.4uA   -145.3uA   -477.4uA
1.275V    -1.74mA    -923.3uA   -3.27mA
2.1V      -7.146mA   -4.219mA   -11.39mA
2.42V     -8.703mA   -5.114mA   -14.14mA
2.875V    -10.39mA   -7.113mA   -16.4mA
3.115V    -11.71mA   -8.164mA   -16.59mA
3.755V    -14.98mA   -10.27mA   -20.66mA
4.125V    -15.94mA   -10.71mA   -22.84mA
4.83V     -16.6mA    -11.12mA   -24.15mA
6.6V      -17.03mA   -11.4mA    -24.88mA
[Ramp]
| IOASDB_DC_33
| variable   typ   min   max
dV/dt_r   1.18/1.38E-09   0.92/1.80E-09   1.44/1.11E-09
dV/dt_f   1.51/1.36E-09   1.29/1.63E-09   1.69/1.32E-09
R_load = 1000
[Rising Waveform]
| IOASDB_DC_33
R_fixture =   1000
C_fixture =   0
L_fixture =   0
V_fixture =   0
V_fixture_min = 0
V_fixture_max = 0
|   Time   V(typ)   V(min)   V(max)
0s        22.96mV    18.97mV    29.38mV
465ps     137.7mV    90.05mV    203mV
1.015ns   457.3mV    302.6mV    648.8mV
1.575ns   911.1mV    619.3mV    1.206V
1.9ns     1.145V     829.7mV    1.855V
2.235ns   1.518V     989mV      2.146V
2.885ns   1.801V     1.257V     2.332V
4.125ns   1.917V     1.452V     2.397V
28.01ns   1.985V     1.559V     2.428V
239.9ns   1.985V     1.56V      2.428V
[Falling Waveform]
| IOASDB_DC_33
R_fixture =   1000
C_fixture =   0
L_fixture =   0
V_fixture =   3.3
V_fixture_min = 3
V_fixture_max = 3.6
|   Time   V(typ)   V(min)   V(max)
0s        3.3V       3V         3.6V
790ps     3.298V     3V         3.577V
1.19ns    3.199V     2.993V     3.182V
1.69ns    2.655V     2.792V     2.431V
2.395ns   1.78V      2.087V     1.552V
3ns       1.255V     1.566V     1.132V
3.77ns    980.8mV    1.204V     988.7mV
4.77ns    871.8mV    987.5mV    914.1mV
8.37ns    816mV      847.2mV    817.9mV
239.9ns   790mV      846.8mV    781.7mV
[Rising Waveform]
| IOASDB_DC_33
R_fixture =   1000
C_fixture =   0
L_fixture =   0
V_fixture =   3.3
V_fixture_min = 3
V_fixture_max = 3.6
|   Time   V(typ)   V(min)   V(max)
0s        790mV      846.8mV    781.7mV
600ps     975.1mV    967.7mV    1.043V
1.475ns   1.59V      1.407V     1.83V
1.77ns    1.851V     1.589V     2.913V
2ns       2.395V     1.716V     3.457V
2.31ns    2.991V     1.919V     3.579V
2.675ns   3.223V     2.375V     3.594V
3.615ns   3.291V     2.916V     3.597V
6.445ns   3.3V       2.998V     3.6V
239.9ns   3.3V       3V         3.6V
[Falling Waveform]
| IOASDB_DC_33
R_fixture =   1000
C_fixture =   0
L_fixture =   0
V_fixture =   0
V_fixture_min = 0
V_fixture_max = 0
|   Time   V(typ)   V(min)   V(max)
0s        1.985V     1.56V      2.428V
890ps     1.943V     1.542V     2.321V
1.585ns   1.657V     1.403V     1.854V
2ns       1.432V     1.229V     1.637V
2.845ns   934.2mV    863mV      978.6mV
4.215ns   538.9mV    518.6mV    550mV
7.16ns    227.3mV    235.1mV    209.9mV
11.82ns   87.94mV    99.21mV    80.86mV
36.89ns   30.29mV    27.24mV    37.12mV
239.9ns   23.76mV    19.77mV    30.38mV
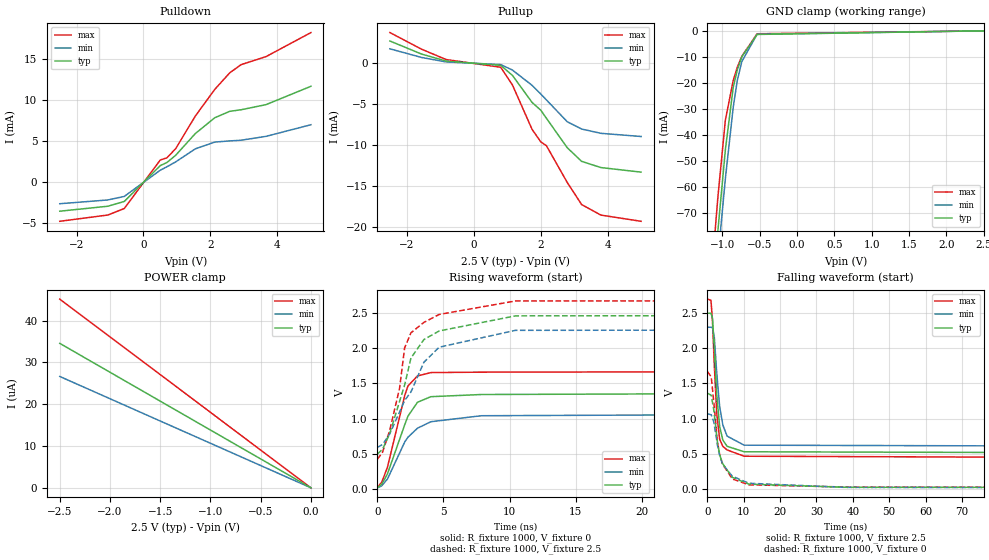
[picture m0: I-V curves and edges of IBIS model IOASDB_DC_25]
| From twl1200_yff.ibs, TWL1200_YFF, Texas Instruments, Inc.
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[Model]   IOASDB_DC_25
Model_type  I/O
Vinl=0.875
Vinh=1.625
Enable   Active-Low
Vref =   2.5
Rref =   1M
Cref =   15p
Vmeas =   1.25
| variable   typ   min   max
C_comp   4.06pF   3.38pF   4.99pF
| C_pullup   4.03pF   3.38pF   4.79pF
| C_pulldown   4.36pF   3.55pF   5.22pF
| C_tri-state   4.06pF   3.38pF   4.99pF
[Temperature Range]   40   100   -40
| Ambient temperature   25   85   -40
[Voltage range]   2.5   2.3   2.7
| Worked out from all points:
|   slope of the pulldown table from 0 to 0.375 V, typ, clamps not added: 235 ohm
|   slope of the pullup table from 0 to 0.375 V, typ, clamps not added: 4.32 kohm
|   GND clamp passes 1 mA (typ) near -0.51 V on its own axis
|   rising waveform, R_fixture 1000, V_fixture 0: 20-80 % time 1.55ns typ, 1.98ns min, 1.25ns max; typ from 0.018 V to 1.36 V
|   falling waveform, R_fixture 1000, V_fixture 2.5: 20-80 % time 1.52ns typ, 1.95ns min, 1.35ns max; typ from 2.5 V to 0.497 V
|   rising waveform, R_fixture 1000, V_fixture 2.5: 20-80 % time 2.22ns typ, 2.92ns min, 1.66ns max; typ from 0.497 V to 2.5 V
|   falling waveform, R_fixture 1000, V_fixture 0: 20-80 % time 3.05ns typ, 3.78ns min, 2.59ns max; typ from 1.36 V to 0.018 V
[GND Clamp]
| IOASDB_DC_25
|   Voltage   I(typ)   I(min)   I(max)
-2.5V     -624.7mA   -607.3mA   -648.7mA
-1.145V   -106mA     -115.5mA   -94.56mA
-1.13V    -100.8mA   -110.5mA   -89.01mA
-1.1V     -90.46mA   -100.7mA   -78.08mA
-1.075V   -82.01mA   -92.54mA   -69.21mA
-1.06V    -77mA      -87.72mA   -64.01mA
-960mV    -45.8mA    -56.97mA   -34.37mA
-855mV    -21.79mA   -29.46mA   -19.15mA
-800mV    -15.04mA   -19.06mA   -14.02mA
-740mV    -10.03mA   -11.86mA   -9.831mA
-535mV    -1.389mA   -1.312mA   -1.131mA
2.5V      522.9pA    2.136uA    -3.613uA
[POWER Clamp]
| IOASDB_DC_25
|   Voltage   I(typ)   I(min)   I(max)
-2.5V     34.57uA    26.65uA    45.15uA
-90mV     1.247uA    966.3nA    1.634uA
-60mV     834.2nA    648.8nA    1.087uA
0V        0A         0A         0A
[Pulldown]
| IOASDB_DC_25
|   Voltage   I(typ)   I(min)   I(max)
-2.5V     -3.51mA    -2.599mA   -4.741mA
-1.065V   -2.904mA   -2.139mA   -3.976mA
-575mV    -2.325mA   -1.709mA   -3.188mA
500mV     2.044mA    1.485mA    2.729mA
700mV     2.427mA    1.907mA    2.997mA
960mV     3.306mA    2.5mA      4.109mA
1.55V     5.964mA    4.098mA    8.103mA
2.13V     7.887mA    4.918mA    11.35mA
2.575V    8.666mA    5.059mA    13.36mA
2.915V    8.858mA    5.143mA    14.36mA
3.66V     9.485mA    5.618mA    15.34mA
5V        11.72mA    7.033mA    18.27mA
[Pullup]
| IOASDB_DC_25
|   Voltage   I(typ)   I(min)   I(max)
-2.5V     2.747mA    1.789mA    3.778mA
-1.55V    1.139mA    725.8uA    1.733mA
-820mV    289uA      183.4uA    474.2uA
810mV     -234.8uA   -141.9uA   -470.9uA
1.16V     -1.468mA   -814.6uA   -2.645mA
1.745V    -4.774mA   -2.681mA   -8.066mA
2.005V    -5.725mA   -3.741mA   -9.6mA
2.175V    -6.72mA    -4.474mA   -10.08mA
2.795V    -10.32mA   -7.135mA   -14.57mA
3.225V    -11.99mA   -8.032mA   -17.28mA
3.8V      -12.75mA   -8.558mA   -18.57mA
5V        -13.31mA   -8.946mA   -19.33mA
[Ramp]
| IOASDB_DC_25
| variable   typ   min   max
dV/dt_r   0.81/1.55E-09   0.63/1.98E-09   0.99/1.25E-09
dV/dt_f   1.20/1.52E-09   1.03/1.95E-09   1.37/1.36E-09
R_load = 1000
[Rising Waveform]
| IOASDB_DC_25
R_fixture =   1000
C_fixture =   0
L_fixture =   0
V_fixture =   0
V_fixture_min = 0
V_fixture_max = 0
|   Time   V(typ)   V(min)   V(max)
0s        17.63mV    14.87mV    22.2mV
335ps     65.32mV    43.87mV    95.51mV
770ps     215.5mV    141.5mV    310.9mV
2.075ns   913.7mV    668.2mV    1.331V
2.32ns    1.036V     735.9mV    1.465V
3.035ns   1.232V     863.2mV    1.607V
4.045ns   1.312V     955.7mV    1.655V
7.87ns    1.343V     1.041V     1.661V
39.51ns   1.363V     1.066V     1.67V
239.9ns   1.363V     1.069V     1.671V
[Falling Waveform]
| IOASDB_DC_25
R_fixture =   1000
C_fixture =   0
L_fixture =   0
V_fixture =   2.5
V_fixture_min = 2.3
V_fixture_max = 2.7
|   Time   V(typ)   V(min)   V(max)
0s        2.5V       2.3V       2.7V
970ps     2.498V     2.3V       2.684V
1.38ns    2.43V      2.295V     2.389V
1.895ns   2.009V     2.154V     1.753V
2.545ns   1.352V     1.658V     1.083V
3.355ns   886.5mV    1.174V     708mV
4.245ns   694mV      907.6mV    605.3mV
5.415ns   606.6mV    751.3mV    554.6mV
10.1ns    528.8mV    622.7mV    465.7mV
239.9ns   496.6mV    590.1mV    421.6mV
[Rising Waveform]
| IOASDB_DC_25
R_fixture =   1000
C_fixture =   0
L_fixture =   0
V_fixture =   2.5
V_fixture_min = 2.3
V_fixture_max = 2.7
|   Time   V(typ)   V(min)   V(max)
0s        496.6mV    590.1mV    421.5mV
390ps     562.3mV    630.7mV    520.2mV
930ps     783.8mV    779.9mV    826.8mV
1.68ns    1.244V     1.093V     1.43V
2.065ns   1.477V     1.257V     2.007V
2.545ns   1.863V     1.38V      2.221V
3.525ns   2.125V     1.802V     2.369V
4.675ns   2.247V     2.016V     2.482V
10.45ns   2.462V     2.256V     2.674V
239.9ns   2.5V       2.3V       2.7V
[Falling Waveform]
| IOASDB_DC_25
R_fixture =   1000
C_fixture =   0
L_fixture =   0
V_fixture =   0
V_fixture_min = 0
V_fixture_max = 0
|   Time   V(typ)   V(min)   V(max)
0s        1.363V     1.069V     1.671V
1.045ns   1.332V     1.055V     1.594V
1.755ns   1.118V     953.3mV    1.232V
2.78ns    650mV      614.7mV    662mV
3.375ns   484.6mV    471.3mV    489.2mV
4.17ns    360mV      355.1mV    352mV
6.85ns    165.1mV    180.4mV    142.3mV
11.42ns   68.3mV     81.19mV    59.08mV
38.01ns   23.6mV     22.24mV    27.65mV
239.9ns   18.32mV    15.63mV    22.91mV
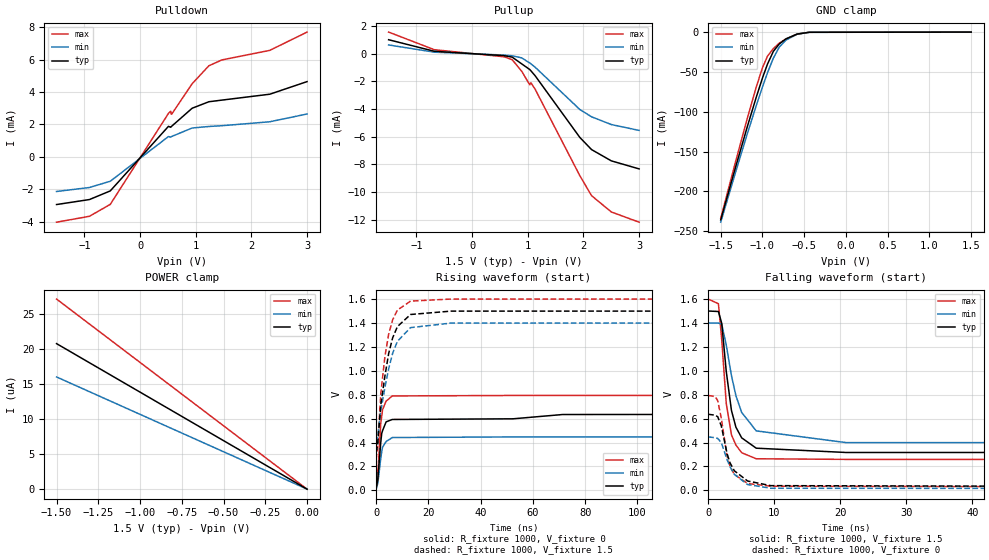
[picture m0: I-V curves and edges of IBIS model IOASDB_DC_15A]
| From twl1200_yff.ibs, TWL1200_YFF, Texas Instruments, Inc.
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[Model]   IOASDB_DC_15A
Model_type  I/O
Vinl=0.525
Vinh=0.975
Enable   Active-Low
Vref =   1.5
Rref =   1M
Cref =   15p
Vmeas =   0.75
| variable   typ   min   max
C_comp   4.28pF   3.66pF   5.02pF
| C_pullup   4.26pF   3.64pF   4.80pF
| C_pulldown   4.58pF   3.80pF   5.24pF
| C_tri-state   4.28pF   3.66pF   5.02pF
[Temperature Range]   40   100   -40
| Ambient temperature   25   85   -40
[Voltage range]   1.5   1.4   1.6
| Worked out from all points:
|   slope of the pulldown table from 0 to 0.225 V, typ, clamps not added: 254 ohm
|   slope of the pullup table from 0 to 0.225 V, typ, clamps not added: 4.42 kohm
|   GND clamp passes 1 mA (typ) near -0.51 V on its own axis
|   rising waveform, R_fixture 1000, V_fixture 0: 20-80 % time 1.81ns typ, 1.57ns min, 1.48ns max; typ from 0.011 V to 0.637 V
|   falling waveform, R_fixture 1000, V_fixture 1.5: 20-80 % time 1.73ns typ, 2.78ns min, 1.28ns max; typ from 1.5 V to 0.317 V
|   rising waveform, R_fixture 1000, V_fixture 1.5: 20-80 % time 4.95ns typ, 5.74ns min, 4.02ns max; typ from 0.317 V to 1.5 V
|   falling waveform, R_fixture 1000, V_fixture 0: 20-80 % time 2.29ns typ, 2.25ns min, 1.69ns max; typ from 0.637 V to 0.012 V
[GND Clamp]
| IOASDB_DC_15A
|   Voltage   I(typ)   I(min)   I(max)
-1.5V     -235.9mA   -238.8mA   -234mA
-1.32V    -168.9mA   -175.3mA   -162mA
-1.18V    -118.3mA   -127.2mA   -107.7mA
-1.075V   -81.99mA   -92.53mA   -69.18mA
-1V       -57.7mA    -68.91mA   -44.76mA
-940mV    -40.23mA   -51.2mA    -30.27mA
-870mV    -24.29mA   -32.87mA   -20.72mA
-800mV    -15.03mA   -19.05mA   -14mA
-720mV    -8.614mA   -10.16mA   -8.634mA
-585mV    -2.51mA    -2.681mA   -2.42mA
-440mV    -273.1uA   -256.5uA   -157.3uA
1.5V      381.3pA    1.072uA    -1.806uA
[POWER Clamp]
| IOASDB_DC_15A
|   Voltage   I(typ)   I(min)   I(max)
-1.5V     20.74uA    15.99uA    27.09uA
-245mV    3.388uA    2.615uA    4.425uA
-55mV     763.2nA    594.2nA    995nA
0V        0A         0A         0A
[Pulldown]
| IOASDB_DC_15A
|   Voltage   I(typ)   I(min)   I(max)
-1.5V     -2.947mA   -2.143mA   -4.037mA
-910mV    -2.64mA    -1.895mA   -3.673mA
-535mV    -2.106mA   -1.51mA    -2.937mA
510mV     1.879mA    1.249mA    2.677mA
550mV     1.825mA    1.215mA    2.814mA
560mV     1.856mA    1.236mA    2.626mA
570mV     1.892mA    1.257mA    2.641mA
935mV     2.996mA    1.776mA    4.507mA
1.235V    3.397mA    1.871mA    5.615mA
1.47V     3.499mA    1.919mA    5.979mA
2.33V     3.863mA    2.162mA    6.568mA
3V        4.641mA    2.641mA    7.698mA
[Pullup]
| IOASDB_DC_15A
|   Voltage   I(typ)   I(min)   I(max)
-1.5V     1.02mA     642.2uA    1.573mA
-680mV    185.2uA    120.3uA    299.3uA
575mV     -132.4uA   -89.35uA   -213.4uA
720mV     -240.1uA   -143.6uA   -425.9uA
890mV     -725.7uA   -293.2uA   -1.259mA
1.035V    -1.135mA   -664.1uA   -2.245mA
1.055V    -1.224mA   -723.8uA   -2.091mA
1.13V     -1.577mA   -960.1uA   -2.55mA
1.935V    -6.049mA   -4.029mA   -8.818mA
2.145V    -6.927mA   -4.556mA   -10.26mA
2.5V      -7.743mA   -5.116mA   -11.44mA
3V        -8.325mA   -5.54mA    -12.18mA
[Ramp]
| IOASDB_DC_15A
| variable   typ   min   max
dV/dt_r   0.38/1.81E-09   0.26/1.57E-09   0.47/1.48E-09
dV/dt_f   0.71/1.73E-09   0.60/2.78E-09   0.80/1.28E-09
R_load = 1000
[Rising Waveform]
| IOASDB_DC_15A
R_fixture =   1000
C_fixture =   0
L_fixture =   0
V_fixture =   0
V_fixture_min = 0
V_fixture_max = 0
|   Time   V(typ)   V(min)   V(max)
0s        11.11mV    9.751mV    13.53mV
640ps     88.94mV    57.56mV    130.6mV
1.79ns    402.9mV    269.3mV    564mV
2.14ns    475mV      322.7mV    620.3mV
2.48ns    499.8mV    361mV      675.6mV
3.825ns   572.8mV    408.1mV    746.1mV
6.2ns     592.8mV    441.7mV    789.5mV
52.4ns    598.3mV    446.8mV    793.6mV
71.38ns   634.2mV    446.8mV    793.7mV
240ns     636.7mV    446.8mV    794.2mV
[Falling Waveform]
| IOASDB_DC_15A
R_fixture =   1000
C_fixture =   0
L_fixture =   0
V_fixture =   1.5
V_fixture_min = 1.4
V_fixture_max = 1.6
|   Time   V(typ)   V(min)   V(max)
0s        1.5V       1.4V       1.6V
1.55ns    1.496V     1.399V     1.561V
2.05ns    1.397V     1.39V      1.26V
2.735ns   994.8mV    1.216V     726.8mV
3.52ns    668.8mV    960.1mV    464.9mV
4.2ns     528.2mV    791.4mV    379.1mV
5.07ns    439.5mV    651.7mV    315mV
7.275ns   353mV      497.8mV    264.6mV
20.86ns   317.2mV    399.9mV    259.4mV
240ns     317.1mV    399mV      258.8mV
[Rising Waveform]
| IOASDB_DC_15A
R_fixture =   1000
C_fixture =   0
L_fixture =   0
V_fixture =   1.5
V_fixture_min = 1.4
V_fixture_max = 1.6
|   Time   V(typ)   V(min)   V(max)
0s        316.9mV    399mV      258.5mV
600ps     389.8mV    443.4mV    367.5mV
1.79ns    714.5mV    663.7mV    810.1mV
3.38ns    957.7mV    863.1mV    1.121V
4.82ns    1.146V     1.018V     1.308V
6.335ns   1.276V     1.147V     1.427V
8.155ns   1.37V      1.247V     1.508V
13.18ns   1.471V     1.361V     1.583V
28.62ns   1.499V     1.399V     1.6V
240ns     1.5V       1.4V       1.6V
[Falling Waveform]
| IOASDB_DC_15A
R_fixture =   1000
C_fixture =   0
L_fixture =   0
V_fixture =   0
V_fixture_min = 0
V_fixture_max = 0
|   Time   V(typ)   V(min)   V(max)
0s        636.7mV    447.4mV    794.4mV
1.07ns    628.9mV    440.4mV    784.1mV
1.445ns   615.8mV    434.5mV    750mV
1.98ns    540.2mV    400.7mV    603.8mV
2.87ns    305.7mV    255.7mV    281.8mV
3.31ns    229.7mV    196.6mV    201.3mV
3.965ns   163.8mV    134.2mV    133.8mV
5.965ns   78.62mV    49.02mV    57.61mV
9.48ns    39.79mV    17.99mV    34.83mV
240ns     11.7mV     10.37mV    14mV
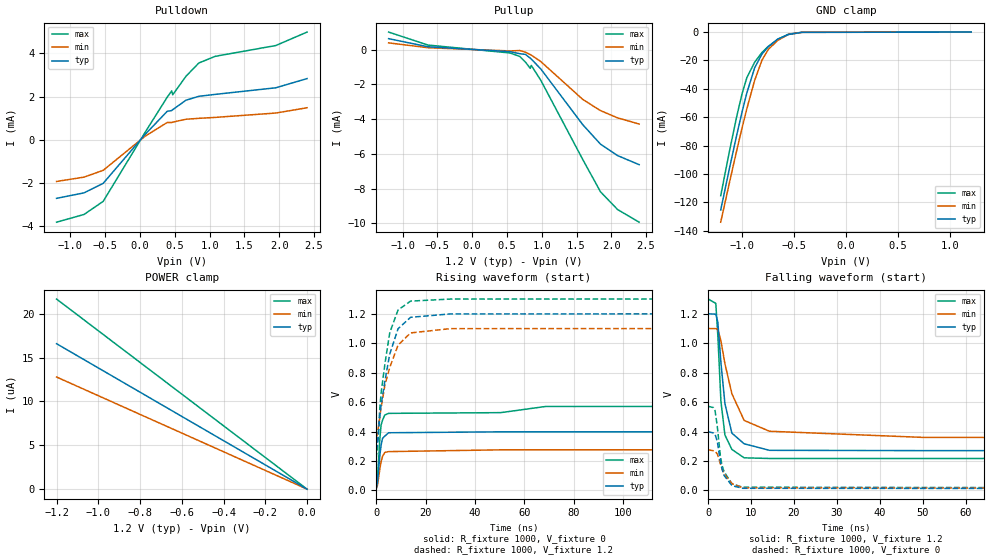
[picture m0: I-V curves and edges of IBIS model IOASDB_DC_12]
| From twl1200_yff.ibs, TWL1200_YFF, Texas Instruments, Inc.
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[Model]   IOASDB_DC_12
Model_type  I/O
Vinl=0.24
Vinh=0.96
Enable   Active-Low
Vref =   1.2
Rref =   1M
Cref =   15p
Vmeas =   0.6
| variable   typ   min   max
C_comp   4.36pF   3.78pF   5.03pF
| C_pullup   4.37pF   3.75pF   4.85pF
| C_pulldown   4.67pF   3.87pF   5.25pF
| C_tri-state   4.36pF   3.78pF   5.03pF
[Temperature Range]   40   100   -40
| Ambient temperature   25   85   -40
[Voltage range]   1.2   1.1   1.3
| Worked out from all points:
|   slope of the pulldown table from 0 to 0.18 V, typ, clamps not added: 272 ohm
|   slope of the pullup table from 0 to 0.18 V, typ, clamps not added: 4.5 kohm
|   GND clamp passes 1 mA (typ) near -0.51 V on its own axis
|   rising waveform, R_fixture 1000, V_fixture 0: 20-80 % time 1.39ns typ, 1.6ns min, 1.63ns max; typ from 0.009 V to 0.398 V
|   falling waveform, R_fixture 1000, V_fixture 1.2: 20-80 % time 2.13ns typ, 4.27ns min, 1.35ns max; typ from 1.2 V to 0.27 V
|   rising waveform, R_fixture 1000, V_fixture 1.2: 20-80 % time 5.55ns typ, 6.3ns min, 4.6ns max; typ from 0.27 V to 1.2 V
|   falling waveform, R_fixture 1000, V_fixture 0: 20-80 % time 1.71ns typ, 2.46ns min, 1.72ns max; typ from 0.398 V to 0.01 V
[GND Clamp]
| IOASDB_DC_12
|   Voltage   I(typ)   I(min)   I(max)
-1.2V     -125.4mA   -134mA     -115.3mA
-1.115V   -95.58mA   -105.6mA   -83.48mA
-1.045V   -72.04mA   -82.92mA   -58.91mA
-995mV    -56.16mA   -67.38mA   -43.31mA
-950mV    -42.96mA   -54.05mA   -32.2mA
-875mV    -25.19mA   -34.06mA   -21.26mA
-805mV    -15.51mA   -19.83mA   -14.41mA
-745mV    -10.38mA   -12.31mA   -10.11mA
-655mV    -4.945mA   -5.886mA   -5.237mA
-550mV    -1.666mA   -1.631mA   -1.426mA
-420mV    -178.9uA   -173.3uA   -100.4uA
1.2V      343.5pA    1.071uA    -1.806uA
[POWER Clamp]
| IOASDB_DC_12
|   Voltage   I(typ)   I(min)   I(max)
-1.2V     16.59uA    12.79uA    21.68uA
-235mV    3.25uA     2.509uA    4.245uA
-55mV     762.8nA    593.8nA    994.6nA
0V        0A         0A         0A
[Pulldown]
| IOASDB_DC_12
|   Voltage   I(typ)   I(min)   I(max)
-1.2V     -2.717mA   -1.935mA   -3.824mA
-805mV    -2.464mA   -1.734mA   -3.465mA
-530mV    -2.023mA   -1.419mA   -2.859mA
75mV      254.2uA    169uA      356.1uA
390mV     1.318mA    798.3uA    1.971mA
455mV     1.353mA    797.5uA    2.263mA
470mV     1.396mA    816.2uA    2.086mA
660mV     1.833mA    950.7uA    2.943mA
845mV     2.014mA    992.4uA    3.559mA
1.08V     2.103mA    1.036mA    3.868mA
1.95V     2.409mA    1.238mA    4.368mA
2.4V      2.835mA    1.483mA    4.992mA
[Pullup]
| IOASDB_DC_12
|   Voltage   I(typ)   I(min)   I(max)
-1.2V     622.9uA    381.2uA    1.002mA
-635mV    158.2uA    102.5uA    255.8uA
545mV     -124.3uA   -83.39uA   -199.9uA
685mV     -241.4uA   -58.42uA   -399.8uA
765mV     -280.8uA   -154.6uA   -719.6uA
835mV     -498.6uA   -289.8uA   -1.084mA
850mV     -552.5uA   -323.8uA   -918.3uA
985mV     -1.111mA   -687.9uA   -1.76mA
1.59V     -4.327mA   -2.873mA   -6.332mA
1.845V    -5.448mA   -3.517mA   -8.19mA
2.09V     -6.105mA   -3.933mA   -9.208mA
2.4V      -6.625mA   -4.29mA    -9.937mA
[Ramp]
| IOASDB_DC_12
| variable   typ   min   max
dV/dt_r   0.23/1.39E-09   0.16/1.60E-09   0.34/1.63E-09
dV/dt_f   0.56/2.13E-09   0.45/4.27E-09   0.65/1.35E-09
R_load = 1000
[Rising Waveform]
| IOASDB_DC_12
R_fixture =   1000
C_fixture =   0
L_fixture =   0
V_fixture =   0
V_fixture_min = 0
V_fixture_max = 0
|   Time   V(typ)   V(min)   V(max)
0s        9.249mV    8.199mV    11.23mV
535ps     52.22mV    32.59mV    79.58mV
1.555ns   243.1mV    150.6mV    359.7mV
2.005ns   305.9mV    194.3mV    443.5mV
2.6ns     353.2mV    230.1mV    476.6mV
3.475ns   368.1mV    257.4mV    511.5mV
5.04ns    391.5mV    263.4mV    523.3mV
50.38ns   397.9mV    275.5mV    528.2mV
68.58ns   397.9mV    275.5mV    570.2mV
240ns     397.9mV    275.5mV    570.6mV
[Falling Waveform]
| IOASDB_DC_12
R_fixture =   1000
C_fixture =   0
L_fixture =   0
V_fixture =   1.2
V_fixture_min = 1.1
V_fixture_max = 1.3
|   Time   V(typ)   V(min)   V(max)
0s        1.2V       1.1V       1.3V
1.77ns    1.197V     1.099V     1.271V
2.245ns   1.144V     1.095V     1.053V
2.97ns    866.9mV    1.016V     605.1mV
3.9ns     589.5mV    860.5mV    376.6mV
5.52ns    389mV      657.1mV    278.4mV
8.375ns   316.7mV    475.6mV    221.2mV
14.29ns   272.2mV    401.8mV    216.8mV
50.12ns   270.2mV    360mV      216.8mV
240ns     270.2mV    358mV      216.8mV
[Rising Waveform]
| IOASDB_DC_12
R_fixture =   1000
C_fixture =   0
L_fixture =   0
V_fixture =   1.2
V_fixture_min = 1.1
V_fixture_max = 1.3
|   Time   V(typ)   V(min)   V(max)
0s        270.2mV    358.1mV    216.7mV
530ps     313.8mV    382.1mV    286mV
1.485ns   498.1mV    496.6mV    554.4mV
1.985ns   577.7mV    557.2mV    657.3mV
3.565ns   743.5mV    717.4mV    859.9mV
5.505ns   925.8mV    834.9mV    1.071V
8.875ns   1.098V     986.7mV    1.226V
13.93ns   1.176V     1.07V      1.286V
29.98ns   1.199V     1.099V     1.3V
240ns     1.2V       1.1V       1.3V
[Falling Waveform]
| IOASDB_DC_12
R_fixture =   1000
C_fixture =   0
L_fixture =   0
V_fixture =   0
V_fixture_min = 0
V_fixture_max = 0
|   Time   V(typ)   V(min)   V(max)
0s        398.3mV    275.6mV    570.9mV
1.22ns    390.4mV    269.3mV    562.9mV
1.61ns    381mV      265.7mV    539.4mV
2.125ns   331.9mV    247.3mV    433.4mV
2.865ns   193.9mV    178.6mV    226.6mV
3.245ns   144.9mV    145.1mV    168.2mV
3.705ns   101.6mV    112.7mV    126.7mV
5.56ns    31.77mV    44.9mV     44.59mV
8.03ns    14.31mV    18.08mV    21.64mV
240ns     9.692mV    8.274mV    11.65mV
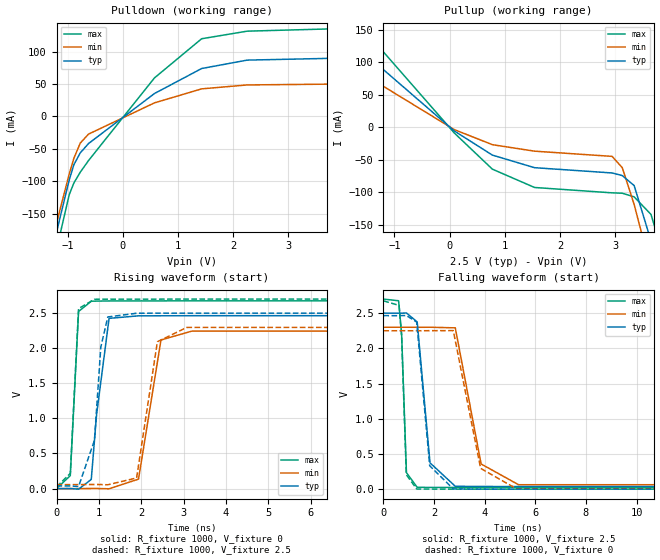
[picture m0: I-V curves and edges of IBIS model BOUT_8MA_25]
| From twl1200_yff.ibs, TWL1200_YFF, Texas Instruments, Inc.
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[Model]   BOUT_8MA_25
Model_type  Output
Vref =   2.5
Rref =   1M
Cref =   15p
Vmeas =   1.25
| variable   typ   min   max
C_comp   4.10pF   2.76pF   5.42pF
| C_pullup   4.40pF   2.76pF   5.42pF
| C_pulldown   3.79pF   3.03pF   4.93pF
[Temperature Range]   40   100   -40
| Ambient temperature   25   85   -40
[Voltage range]   2.5   2.3   2.7
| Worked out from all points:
|   slope of the pulldown table from 0 to 0.375 V, typ, clamps not added: 15.8 ohm
|   slope of the pullup table from 0 to 0.375 V, typ, clamps not added: 15.8 ohm
|   rising waveform, R_fixture 1000, V_fixture 0: 20-80 % time 171ps typ, 262ps min, 101ps max; typ from 0 V to 2.46 V
|   falling waveform, R_fixture 1000, V_fixture 2.5: 20-80 % time 306ps typ, 513ps min, 127ps max; typ from 2.5 V to 0.037 V
|   rising waveform, R_fixture 1000, V_fixture 2.5: 20-80 % time 167ps typ, 252ps min, 99.2ps max; typ from 0.037 V to 2.5 V
|   falling waveform, R_fixture 1000, V_fixture 0: 20-80 % time 300ps typ, 502ps min, 124ps max; typ from 2.46 V to 0 V
[Pulldown]
| BOUT_8MA_25
|   Voltage   I(typ)   I(min)   I(max)
-2.5V     -690.3mA   -641.5mA   -763mA
-1.245V   -196.5mA   -181mA     -226.5mA
-1.19V    -175.8mA   -161.9mA   -203.6mA
-1.14V    -157.3mA   -144.7mA   -183.2mA
-970mV    -98.03mA   -88.92mA   -120.7mA
-885mV    -74.36mA   -64.43mA   -102.6mA
-770mV    -56.23mA   -41.12mA   -86.03mA
-620mV    -41.83mA   -27.27mA   -68.05mA
575mV     35.31mA    20.91mA    59.4mA
1.43V     73.88mA    42.51mA    119.8mA
2.255V    86.85mA    48.56mA    131.5mA
5V        91.85mA    50.86mA    137.9mA
[Pullup]
| BOUT_8MA_25
|   Voltage   I(typ)   I(min)   I(max)
-2.5V     182.5mA    132.1mA    229mA
-1.685V   124.1mA    87.9mA     162.9mA
85mV      -5.859mA   -3.785mA   -8.983mA
775mV     -43.04mA   -26.99mA   -64.67mA
1.54V     -62.39mA   -36.98mA   -92.85mA
2.945V    -70.5mA    -44.99mA   -101.1mA
3.13V     -74.54mA   -62.43mA   -101.7mA
3.345V    -89.98mA   -119mA     -107.3mA
3.65V     -174.9mA   -218.7mA   -134.3mA
3.76V     -213.2mA   -256.3mA   -165.3mA
3.895V    -261.6mA   -303.2mA   -213.5mA
5V        -678.1mA   -700.7mA   -652.5mA
[Ramp]
| BOUT_8MA_25
| variable   typ   min   max
dV/dt_r   1.49/1.93E-10   1.36/2.72E-10   1.61/1.10E-10
dV/dt_f   1.48/3.21E-10   1.35/5.20E-10   1.61/1.30E-10
R_load = 1000
[Rising Waveform]
| BOUT_8MA_25
R_fixture =   1000
C_fixture =   0
L_fixture =   0
V_fixture =   0
V_fixture_min = 0
V_fixture_max = 0
|   Time   V(typ)   V(min)   V(max)
0s        8.384nV    35.52nV    717pV
325ps     1.37mV     -24.3uV    184.4mV
520ps     -8.176mV   -48.55uV   2.523V
820ps     130.5mV    1.236mV    2.669V
945ps     1.052V     1.819mV    2.671V
1.24ns    2.425V     -2.688mV   2.673V
1.935ns   2.461V     134.9mV    2.674V
2.465ns   2.462V     2.117V     2.674V
3.19ns    2.463V     2.243V     2.675V
238.2ns   2.465V     2.25V      2.675V
[Falling Waveform]
| BOUT_8MA_25
R_fixture =   1000
C_fixture =   0
L_fixture =   0
V_fixture =   2.5
V_fixture_min = 2.3
V_fixture_max = 2.7
|   Time   V(typ)   V(min)   V(max)
0s        2.5V       2.3V       2.7V
600ps     2.499V     2.3V       2.676V
720ps     2.5V       2.3V       2.204V
910ps     2.502V     2.3V       235.1mV
1.335ns   2.375V     2.299V     25.94mV
1.84ns    374.3mV    2.3V       24.61mV
2.84ns    40.78mV    2.291V     23.95mV
3.86ns    37.96mV    357.8mV    23.71mV
5.34ns    37.41mV    63.11mV    23.59mV
238.2ns   37.17mV    56.86mV    23.53mV
[Rising Waveform]
| BOUT_8MA_25
R_fixture =   1000
C_fixture =   0
L_fixture =   0
V_fixture =   2.5
V_fixture_min = 2.3
V_fixture_max = 2.7
|   Time   V(typ)   V(min)   V(max)
0s        37.17mV    56.86mV    23.53mV
325ps     38.39mV    56.84mV    217.6mV
520ps     29.09mV    56.82mV    2.564V
895ps     687.6mV    58.37mV    2.697V
1.045ns   2.016V     57.8mV     2.698V
1.21ns    2.445V     54.49mV    2.698V
1.89ns    2.498V     151.5mV    2.699V
2.38ns    2.499V     2.092V     2.699V
3.075ns   2.499V     2.296V     2.7V
238.2ns   2.5V       2.3V       2.7V
[Falling Waveform]
| BOUT_8MA_25
R_fixture =   1000
C_fixture =   0
L_fixture =   0
V_fixture =   0
V_fixture_min = 0
V_fixture_max = 0
|   Time   V(typ)   V(min)   V(max)
0s        2.465V     2.25V      2.675V
620ps     2.464V     2.25V      2.61V
720ps     2.465V     2.25V      2.166V
905ps     2.467V     2.25V      205.4mV
1.315ns   2.373V     2.249V     2.233mV
1.83ns    331.4mV    2.251V     990.1uV
2.76ns    3.545mV    2.252V     417.4uV
3.84ns    707uV      295.9mV    175.8uV
5.255ns   237.9uV    5.986mV    63.05uV
238.2ns   19.88nV    53.75nV    5.961nV
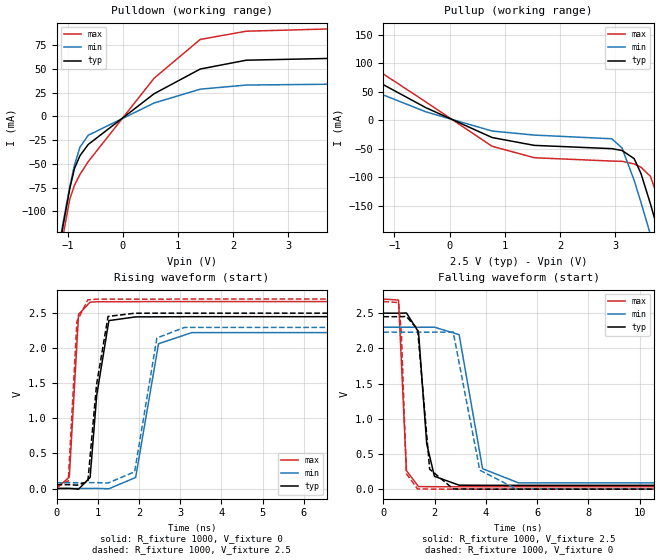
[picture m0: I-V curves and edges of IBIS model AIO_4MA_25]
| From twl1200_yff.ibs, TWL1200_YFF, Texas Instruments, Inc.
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[Model]   AIO_4MA_25
Model_type  Output
Vref =   2.5
Rref =   1M
Cref =   15p
Vmeas =   1.25
| variable   typ   min   max
C_comp   3.62pF   2.68pF   4.78pF
| C_pullup   3.86pF   2.68pF   4.78pF
| C_pulldown   3.38pF   2.88pF   3.93pF
[Temperature Range]   40   100   -40
| Ambient temperature   25   85   -40
[Voltage range]   2.5   2.3   2.7
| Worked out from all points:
|   slope of the pulldown table from 0 to 0.375 V, typ, clamps not added: 23.1 ohm
|   slope of the pullup table from 0 to 0.375 V, typ, clamps not added: 22.2 ohm
|   rising waveform, R_fixture 1000, V_fixture 0: 20-80 % time 196ps typ, 311ps min, 117ps max; typ from 0 V to 2.45 V
|   falling waveform, R_fixture 1000, V_fixture 2.5: 20-80 % time 296ps typ, 492ps min, 130ps max; typ from 2.5 V to 0.054 V
|   rising waveform, R_fixture 1000, V_fixture 2.5: 20-80 % time 181ps typ, 294ps min, 115ps max; typ from 0.054 V to 2.5 V
|   falling waveform, R_fixture 1000, V_fixture 0: 20-80 % time 288ps typ, 477ps min, 127ps max; typ from 2.45 V to 0 V
[Pulldown]
| AIO_4MA_25
|   Voltage   I(typ)   I(min)   I(max)
-2.5V     -646.8mA   -614mA     -695.8mA
-1.145V   -137.1mA   -132.8mA   -149.3mA
-1.105V   -123.1mA   -119.6mA   -134.3mA
-1.08V    -114.6mA   -111.5mA   -125.1mA
-960mV    -76.07mA   -74.26mA   -87.05mA
-875mV    -54.83mA   -51.19mA   -72.56mA
-775mV    -41.29mA   -32.28mA   -61.08mA
-625mV    -29.5mA    -19.8mA    -47.56mA
570mV     23.99mA    14.19mA    40.37mA
1.405V    49.97mA    28.75mA    81.18mA
2.24V     59.27mA    33.09mA    89.82mA
5V        62.72mA    34.67mA    94.24mA
[Pullup]
| AIO_4MA_25
|   Voltage   I(typ)   I(min)   I(max)
-2.5V     130mA      93.97mA    163.5mA
-430mV    21.91mA    14.65mA    31.96mA
770mV     -30.37mA   -19.01mA   -45.69mA
1.535V    -44.12mA   -26.1mA    -65.78mA
2.94V     -49.87mA   -32.57mA   -71.64mA
3.125V    -53.09mA   -48.77mA   -72.04mA
3.345V    -67.36mA   -105.4mA   -76.58mA
3.47V     -93.89mA   -144.5mA   -82.6mA
3.64V     -146.7mA   -200.3mA   -98.43mA
3.795V    -199.4mA   -252.6mA   -141.3mA
3.95V     -254mA     -305.7mA   -196.1mA
5V        -640.1mA   -677.1mA   -599.8mA
[Ramp]
| AIO_4MA_25
| variable   typ   min   max
dV/dt_r   1.48/2.16E-10   1.35/3.16E-10   1.61/1.24E-10
dV/dt_f   1.47/3.06E-10   1.34/5.00E-10   1.60/1.31E-10
R_load = 1000
[Rising Waveform]
| AIO_4MA_25
R_fixture =   1000
C_fixture =   0
L_fixture =   0
V_fixture =   0
V_fixture_min = 0
V_fixture_max = 0
|   Time   V(typ)   V(min)   V(max)
0s        9.669nV    39.64nV    988pV
310ps     1.509mV    -21.23uV   162.8mV
535ps     -9.333mV   -43.86uV   2.482V
815ps     158mV      1.198mV    2.656V
975ps     1.327V     1.817mV    2.661V
1.27ns    2.393V     -3.574mV   2.662V
1.92ns    2.446V     157.5mV    2.663V
2.475ns   2.447V     2.063V     2.664V
3.28ns    2.449V     2.222V     2.664V
238.2ns   2.45V      2.23V      2.665V
[Falling Waveform]
| AIO_4MA_25
R_fixture =   1000
C_fixture =   0
L_fixture =   0
V_fixture =   2.5
V_fixture_min = 2.3
V_fixture_max = 2.7
|   Time   V(typ)   V(min)   V(max)
0s        2.5V       2.3V       2.7V
590ps     2.499V     2.3V       2.686V
900ps     2.502V     2.3V       263.1mV
1.37ns    2.233V     2.299V     36.64mV
1.69ns    646.4mV    2.3V       35.59mV
1.99ns    182.8mV    2.301V     35.25mV
2.955ns   56.7mV     2.194V     34.65mV
3.87ns    54.82mV    290.7mV    34.45mV
5.275ns   54.27mV    88.96mV    34.32mV
238.2ns   54mV       82.44mV    34.26mV
[Rising Waveform]
| AIO_4MA_25
R_fixture =   1000
C_fixture =   0
L_fixture =   0
V_fixture =   2.5
V_fixture_min = 2.3
V_fixture_max = 2.7
|   Time   V(typ)   V(min)   V(max)
0s        54mV       82.44mV    34.26mV
285ps     55.41mV    82.42mV    106mV
495ps     47.59mV    82.4mV     2.382V
760ps     97.66mV    83.11mV    2.689V
970ps     1.475V     83.79mV    2.698V
1.25ns    2.452V     78.77mV    2.699V
1.895ns   2.498V     238mV      2.699V
2.435ns   2.499V     2.145V     2.699V
3.105ns   2.499V     2.296V     2.7V
238.2ns   2.5V       2.3V       2.7V
[Falling Waveform]
| AIO_4MA_25
R_fixture =   1000
C_fixture =   0
L_fixture =   0
V_fixture =   0
V_fixture_min = 0
V_fixture_max = 0
|   Time   V(typ)   V(min)   V(max)
0s        2.45V      2.23V      2.665V
590ps     2.45V      2.23V      2.65V
700ps     2.45V      2.23V      2.229V
895ps     2.453V     2.23V      219.5mV
1.335ns   2.273V     2.229V     2.543mV
1.805ns   283.7mV    2.23V      1.032mV
2.725ns   3.33mV     2.231V     442.2uV
3.76ns    753.3uV    269.7mV    192.7uV
5.17ns    255uV      6.101mV    69.59uV
238.2ns   43.88nV    92.26nV    17.01nV
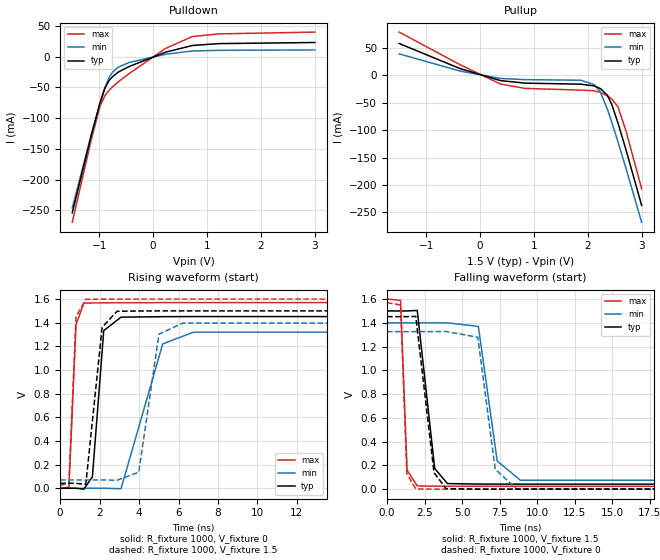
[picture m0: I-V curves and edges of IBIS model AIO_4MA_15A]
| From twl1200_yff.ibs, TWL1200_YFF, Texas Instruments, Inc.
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[Model]   AIO_4MA_15A
Model_type  Output
Vref =   1.5
Rref =   1M
Cref =   15p
Vmeas =   0.75
| variable   typ   min   max
C_comp   3.90pF   2.89pF   4.79pF
| C_pullup   4.06pF   2.89pF   4.79pF
| C_pulldown   3.74pF   3.14pF   4.29pF
[Temperature Range]   40   100   -40
| Ambient temperature   25   85   -40
[Voltage range]   1.5   1.4   1.6
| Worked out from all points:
|   slope of the pulldown table from 0 to 0.225 V, typ, clamps not added: 30.9 ohm
|   slope of the pullup table from 0 to 0.225 V, typ, clamps not added: 36.5 ohm
|   rising waveform, R_fixture 1000, V_fixture 0: 20-80 % time 334ps typ, 603ps min, 203ps max; typ from 0 V to 1.45 V
|   falling waveform, R_fixture 1000, V_fixture 1.5: 20-80 % time 367ps typ, 681ps min, 208ps max; typ from 1.5 V to 0.042 V
|   rising waveform, R_fixture 1000, V_fixture 1.5: 20-80 % time 321ps typ, 558ps min, 199ps max; typ from 0.042 V to 1.5 V
|   falling waveform, R_fixture 1000, V_fixture 0: 20-80 % time 356ps typ, 651ps min, 200ps max; typ from 1.45 V to 0 V
[Pulldown]
| AIO_4MA_15A
|   Voltage   I(typ)   I(min)   I(max)
-1.5V     -254.2mA   -246.1mA   -269.5mA
-1.145V   -127.3mA   -125.9mA   -134.1mA
-985mV    -75mA      -75.69mA   -80.56mA
-895mV    -51.16mA   -50.69mA   -63.37mA
-815mV    -38.33mA   -33.33mA   -54.46mA
-745mV    -31.79mA   -24.14mA   -48.27mA
-640mV    -24.58mA   -16.59mA   -40.27mA
-440mV    -15.72mA   -9.19mA    -27.15mA
225mV     7.289mA    3.957mA    13.31mA
730mV     18.4mA     9.446mA    32.94mA
1.225V    21.44mA    10.49mA    37.29mA
3V        23.24mA    11.13mA    40.2mA
[Pullup]
| AIO_4MA_15A
|   Voltage   I(typ)   I(min)   I(max)
-1.5V     58.43mA    39.5mA     79.24mA
-375mV    12.81mA    8.188mA    20.01mA
380mV     -9.351mA   -5.433mA   -15.65mA
840mV     -13.96mA   -7.606mA   -23.59mA
1.87V     -15.9mA    -8.651mA   -26.73mA
2.12V     -19.02mA   -16.68mA   -27.87mA
2.235V    -24.09mA   -30.33mA   -31.12mA
2.365V    -36.06mA   -61.71mA   -37.2mA
2.445V    -52.99mA   -85.05mA   -42.83mA
2.56V     -86.46mA   -120.9mA   -56.97mA
2.705V    -134.1mA   -168.1mA   -99.46mA
3V        -237.2mA   -267.9mA   -206.6mA
[Ramp]
| AIO_4MA_15A
| variable   typ   min   max
dV/dt_r   0.88/3.45E-10   0.81/6.15E-10   0.95/2.08E-10
dV/dt_f   0.88/3.74E-10   0.80/6.90E-10   0.95/2.26E-10
R_load = 1000
[Rising Waveform]
| AIO_4MA_15A
R_fixture =   1000
C_fixture =   0
L_fixture =   0
V_fixture =   0
V_fixture_min = 0
V_fixture_max = 0
|   Time   V(typ)   V(min)   V(max)
0s        8.038nV    44.31nV    662.6pV
445ps     575.3uV    -165.3nV   9.021mV
805ps     507.8uV    -12.28uV   1.384V
1.205ns   -7.248mV   -35.84uV   1.567V
1.635ns   97.53mV    389.4uV    1.567V
2.21ns    1.333V     684.6uV    1.568V
3.085ns   1.447V     -3.479mV   1.569V
5.2ns     1.451V     1.221V     1.57V
6.76ns    1.452V     1.32V      1.57V
237.8ns   1.452V     1.326V     1.57V
[Falling Waveform]
| AIO_4MA_15A
R_fixture =   1000
C_fixture =   0
L_fixture =   0
V_fixture =   1.5
V_fixture_min = 1.4
V_fixture_max = 1.6
|   Time   V(typ)   V(min)   V(max)
0s        1.5V       1.4V       1.6V
900ps     1.5V       1.4V       1.589V
1.335ns   1.5V       1.4V       160.1mV
2.015ns   1.504V     1.4V       27.27mV
3.175ns   174.7mV    1.4V       25.1mV
4.025ns   46.89mV    1.4V       24.85mV
6.085ns   42.91mV    1.37V      24.67mV
7.34ns    42.44mV    236.9mV    24.64mV
8.885ns   42.26mV    75.21mV    24.62mV
237.8ns   42.16mV    70.83mV    24.62mV
[Rising Waveform]
| AIO_4MA_15A
R_fixture =   1000
C_fixture =   0
L_fixture =   0
V_fixture =   1.5
V_fixture_min = 1.4
V_fixture_max = 1.6
|   Time   V(typ)   V(min)   V(max)
0s        42.16mV    70.83mV    24.62mV
445ps     42.69mV    70.83mV    45.6mV
805ps     41.97mV    70.82mV    1.45V
1.3ns     33.09mV    70.83mV    1.598V
2.13ns    1.362V     70.6mV     1.599V
2.885ns   1.497V     67.95mV    1.599V
3.985ns   1.499V     136.3mV    1.6V
5.01ns    1.5V       1.303V     1.6V
6.21ns    1.5V       1.397V     1.6V
237.8ns   1.5V       1.4V       1.6V
[Falling Waveform]
| AIO_4MA_15A
R_fixture =   1000
C_fixture =   0
L_fixture =   0
V_fixture =   0
V_fixture_min = 0
V_fixture_max = 0
|   Time   V(typ)   V(min)   V(max)
0s        1.452V     1.326V     1.57V
905ps     1.452V     1.326V     1.55V
1.32ns    1.452V     1.326V     131.6mV
1.915ns   1.454V     1.326V     2.489mV
3.13ns    139mV      1.326V     419.8uV
3.935ns   4.159mV    1.327V     220.6uV
6.045ns   616.3uV    1.279V     50.37uV
7.21ns    258.7uV    167.9mV    23.48uV
8.615ns   104.6uV    3.547mV    9.496uV
237.8ns   15.43nV    46.83nV    15.27nV
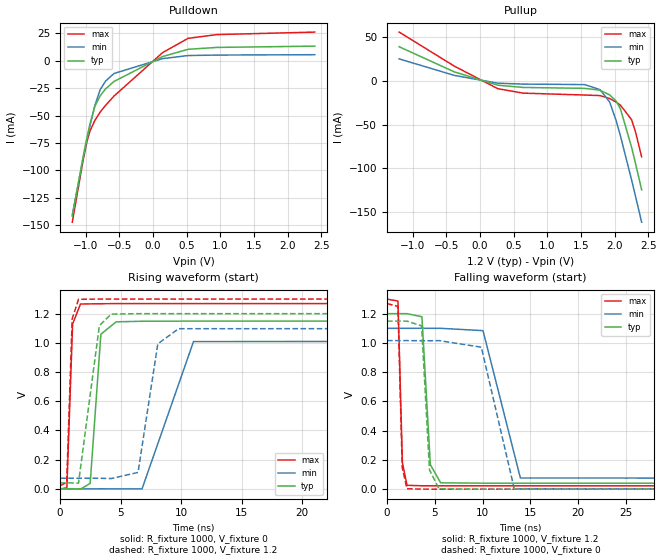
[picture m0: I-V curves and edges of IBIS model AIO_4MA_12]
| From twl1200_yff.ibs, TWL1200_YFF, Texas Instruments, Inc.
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[Model]   AIO_4MA_12
Model_type  Output
Vref =   1.2
Rref =   1M
Cref =   15p
Vmeas =   0.6
| variable   typ   min   max
C_comp   3.95pF   2.88pF   4.72pF
| C_pullup   4.03pF   2.88pF   4.72pF
| C_pulldown   3.86pF   3.18pF   4.47pF
[Temperature Range]   40   100   -40
| Ambient temperature   25   85   -40
[Voltage range]   1.2   1.1   1.3
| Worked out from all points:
|   slope of the pulldown table from 0 to 0.18 V, typ, clamps not added: 38.2 ohm
|   slope of the pullup table from 0 to 0.18 V, typ, clamps not added: 50.1 ohm
|   rising waveform, R_fixture 1000, V_fixture 0: 20-80 % time 478ps typ, 999ps min, 260ps max; typ from 0 V to 1.15 V
|   falling waveform, R_fixture 1000, V_fixture 1.2: 20-80 % time 465ps typ, 983ps min, 245ps max; typ from 1.2 V to 0.041 V
|   rising waveform, R_fixture 1000, V_fixture 1.2: 20-80 % time 451ps typ, 909ps min, 253ps max; typ from 0.041 V to 1.2 V
|   falling waveform, R_fixture 1000, V_fixture 0: 20-80 % time 448ps typ, 923ps min, 239ps max; typ from 1.15 V to 0 V
[Pulldown]
| AIO_4MA_12
|   Voltage   I(typ)   I(min)   I(max)
-1.2V     -141.6mA   -140.6mA   -147.1mA
-1.035V   -86.33mA   -87.82mA   -89.29mA
-985mV    -70.95mA   -72.76mA   -74.54mA
-940mV    -58.27mA   -59.89mA   -64.45mA
-865mV    -41.66mA   -40.8mA    -54.43mA
-785mV    -31.9mA    -26.27mA   -46.71mA
-705mV    -25.62mA   -18.56mA   -40.65mA
-580mV    -18.91mA   -11.64mA   -32.19mA
140mV     3.759mA    1.876mA    7.325mA
520mV     10.38mA    4.699mA    20.37mA
945mV     12.09mA    5.128mA    23.77mA
2.4V      13.26mA    5.469mA    26.06mA
[Pullup]
| AIO_4MA_12
|   Voltage   I(typ)   I(min)   I(max)
-1.2V     39.25mA    25.31mA    56.04mA
-380mV    10.39mA    6.347mA    16.94mA
265mV     -4.877mA   -2.587mA   -8.855mA
640mV     -7.444mA   -3.597mA   -13.98mA
1.555V    -8.504mA   -4.18mA    -16.16mA
1.78V     -10.56mA   -9.904mA   -16.76mA
1.925V    -16.01mA   -24.08mA   -20.1mA
2.02V     -22.91mA   -45.1mA    -24.19mA
2.085V    -31.94mA   -62.88mA   -27.73mA
2.25V     -75.74mA   -113.2mA   -44.32mA
2.31V     -94.86mA   -132.5mA   -58.64mA
2.4V      -124.8mA   -162mA     -87.04mA
[Ramp]
| AIO_4MA_12
| variable   typ   min   max
dV/dt_r   0.70/4.90E-10   0.62/1.01E-09   0.77/2.73E-10
dV/dt_f   0.70/4.74E-10   0.62/9.91E-10   0.77/2.60E-10
R_load = 1000
[Rising Waveform]
| AIO_4MA_12
R_fixture =   1000
C_fixture =   0
L_fixture =   0
V_fixture =   0
V_fixture_min = 0
V_fixture_max = 0
|   Time   V(typ)   V(min)   V(max)
0s        8.358nV    52.74nV    608.3pV
555ps     120.4uV    408.1nV    7.051mV
1.03ns    500.3uV    -1.01uV    1.129V
1.68ns    -1.968mV   -17.8uV    1.266V
2.48ns    37.61mV    42.97uV    1.267V
3.365ns   1.059V     496.6uV    1.268V
4.625ns   1.144V     93.5uV     1.269V
6.765ns   1.148V     -429.5uV   1.269V
11.02ns   1.149V     1.009V     1.269V
237.3ns   1.149V     1.016V     1.269V
[Falling Waveform]
| AIO_4MA_12
R_fixture =   1000
C_fixture =   0
L_fixture =   0
V_fixture =   1.2
V_fixture_min = 1.1
V_fixture_max = 1.3
|   Time   V(typ)   V(min)   V(max)
0s        1.2V       1.1V       1.3V
1.145ns   1.2V       1.1V       1.286V
1.605ns   1.2V       1.1V       184mV
2.095ns   1.2V       1.1V       26.38mV
3.65ns    1.179V     1.1V       23.31mV
4.53ns    168mV      1.1V       23.05mV
5.61ns    43.36mV    1.1V       22.92mV
10.04ns   41.04mV    1.084V     22.82mV
13.95ns   40.83mV    76.34mV    22.82mV
237.3ns   40.8mV     73mV       22.82mV
[Rising Waveform]
| AIO_4MA_12
R_fixture =   1000
C_fixture =   0
L_fixture =   0
V_fixture =   1.2
V_fixture_min = 1.1
V_fixture_max = 1.3
|   Time   V(typ)   V(min)   V(max)
0s        40.8mV     73mV       22.82mV
540ps     40.91mV    73mV       42.89mV
995ps     40.66mV    73mV       1.164V
1.515ns   39.27mV    73mV       1.298V
3.24ns    1.118V     72.52mV    1.3V
4.225ns   1.197V     70.84mV    1.3V
6.435ns   1.2V       112.7mV    1.3V
8.07ns    1.2V       993.4mV    1.3V
9.785ns   1.2V       1.097V     1.3V
237.3ns   1.2V       1.1V       1.3V
[Falling Waveform]
| AIO_4MA_12
R_fixture =   1000
C_fixture =   0
L_fixture =   0
V_fixture =   0
V_fixture_min = 0
V_fixture_max = 0
|   Time   V(typ)   V(min)   V(max)
0s        1.149V     1.016V     1.269V
1.14ns    1.149V     1.016V     1.25V
1.59ns    1.149V     1.016V     149.2mV
2.08ns    1.149V     1.016V     2.941mV
3.615ns   1.117V     1.015V     406.5uV
4.445ns   131.4mV    1.015V     212.8uV
5.44ns    1.911mV    1.016V     105.5uV
9.865ns   209.2uV    970.9mV    6.071uV
13.31ns   26.27uV    2.414mV    698.4nV
237.3ns   8.937nV    51.44nV    6.32nV
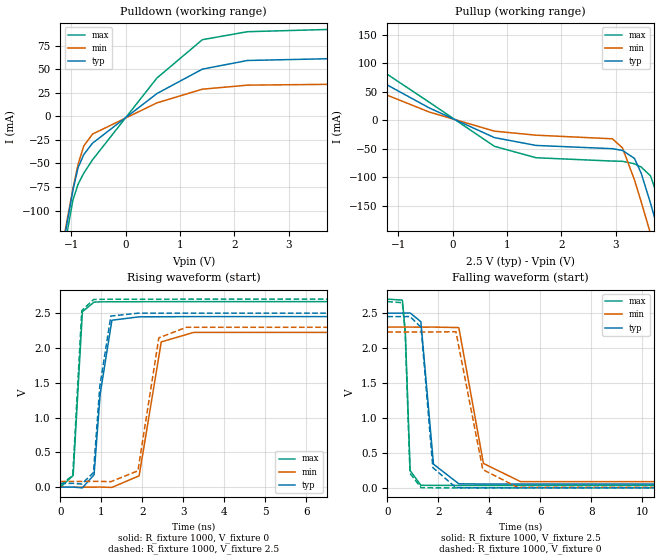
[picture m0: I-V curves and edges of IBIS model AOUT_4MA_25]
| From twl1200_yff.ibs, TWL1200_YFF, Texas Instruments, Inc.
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[Model]   AOUT_4MA_25
Model_type  Output
Vref =   2.5
Rref =   1M
Cref =   15p
Vmeas =   1.25
| variable   typ   min   max
C_comp   3.40pF   2.49pF   4.51pF
| C_pullup   3.64pF   2.49pF   4.51pF
| C_pulldown   3.15pF   2.72pF   3.73pF
[Temperature Range]   40   100   -40
| Ambient temperature   25   85   -40
[Voltage range]   2.5   2.3   2.7
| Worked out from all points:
|   slope of the pulldown table from 0 to 0.375 V, typ, clamps not added: 23.1 ohm
|   slope of the pullup table from 0 to 0.375 V, typ, clamps not added: 22.2 ohm
|   rising waveform, R_fixture 1000, V_fixture 0: 20-80 % time 186ps typ, 294ps min, 112ps max; typ from 0 V to 2.45 V
|   falling waveform, R_fixture 1000, V_fixture 2.5: 20-80 % time 289ps typ, 475ps min, 126ps max; typ from 2.5 V to 0.054 V
|   rising waveform, R_fixture 1000, V_fixture 2.5: 20-80 % time 171ps typ, 278ps min, 109ps max; typ from 0.054 V to 2.5 V
|   falling waveform, R_fixture 1000, V_fixture 0: 20-80 % time 278ps typ, 462ps min, 122ps max; typ from 2.45 V to 0 V
[Pulldown]
| AOUT_4MA_25
|   Voltage   I(typ)   I(min)   I(max)
-2.5V     -642.6mA   -610.7mA   -690.5mA
-1.15V    -137.8mA   -133.6mA   -149.9mA
-1.11V    -123.9mA   -120.4mA   -134.9mA
-1.085V   -115.3mA   -112.3mA   -125.8mA
-970mV    -78.33mA   -76.64mA   -88.69mA
-875mV    -54.32mA   -50.76mA   -71.95mA
-770mV    -40.49mA   -31.37mA   -60.2mA
-610mV    -28.5mA    -18.85mA   -46.14mA
575mV     24.18mA    14.3mA     40.68mA
1.41V     50.08mA    28.8mA     81.33mA
2.24V     59.27mA    33.09mA    89.82mA
5V        62.72mA    34.67mA    94.24mA
[Pullup]
| AOUT_4MA_25
|   Voltage   I(typ)   I(min)   I(max)
-2.5V     130mA      93.97mA    163.5mA
-430mV    21.91mA    14.65mA    31.96mA
770mV     -30.37mA   -19.01mA   -45.69mA
1.535V    -44.12mA   -26.1mA    -65.78mA
2.94V     -49.86mA   -32.46mA   -71.64mA
3.125V    -52.97mA   -48.42mA   -72.03mA
3.345V    -66.91mA   -104.7mA   -76.4mA
3.47V     -93.2mA    -143.6mA   -82.2mA
3.64V     -145.6mA   -199.1mA   -97.66mA
3.795V    -198.1mA   -251.1mA   -140.1mA
3.95V     -252.3mA   -304mA     -194.5mA
5V        -635.9mA   -673.3mA   -595.2mA
[Ramp]
| AOUT_4MA_25
| variable   typ   min   max
dV/dt_r   1.48/2.02E-10   1.35/3.05E-10   1.61/1.19E-10
dV/dt_f   1.47/2.94E-10   1.34/4.85E-10   1.60/1.27E-10
R_load = 1000
[Rising Waveform]
| AOUT_4MA_25
R_fixture =   1000
C_fixture =   0
L_fixture =   0
V_fixture =   0
V_fixture_min = 0
V_fixture_max = 0
|   Time   V(typ)   V(min)   V(max)
0s        9.079nV    37.27nV    970.3pV
310ps     1.537mV    -21.75uV   167.8mV
535ps     -9.551mV   -44.8uV    2.52V
820ps     179.2mV    1.28mV     2.657V
970ps     1.341V     1.868mV    2.661V
1.255ns   2.397V     -3.227mV   2.662V
1.92ns    2.446V     163.6mV    2.663V
2.46ns    2.447V     2.086V     2.664V
3.25ns    2.449V     2.222V     2.664V
238.2ns   2.45V      2.23V      2.665V
[Falling Waveform]
| AOUT_4MA_25
R_fixture =   1000
C_fixture =   0
L_fixture =   0
V_fixture =   2.5
V_fixture_min = 2.3
V_fixture_max = 2.7
|   Time   V(typ)   V(min)   V(max)
0s        2.5V       2.3V       2.7V
590ps     2.499V     2.3V       2.686V
705ps     2.5V       2.3V       2.232V
895ps     2.502V     2.3V       247.5mV
1.315ns   2.378V     2.299V     37mV
1.81ns    339mV      2.3V       35.44mV
2.805ns   57.7mV     2.293V     34.71mV
3.77ns    54.88mV    349.4mV    34.46mV
5.225ns   54.27mV    89.05mV    34.33mV
238.2ns   54mV       82.44mV    34.26mV
[Rising Waveform]
| AOUT_4MA_25
R_fixture =   1000
C_fixture =   0
L_fixture =   0
V_fixture =   2.5
V_fixture_min = 2.3
V_fixture_max = 2.7
|   Time   V(typ)   V(min)   V(max)
0s        54mV       82.44mV    34.26mV
300ps     55.39mV    82.42mV    168mV
520ps     45.75mV    82.4mV     2.535V
805ps     209.2mV    83.47mV    2.694V
960ps     1.446V     83.86mV    2.697V
1.23ns    2.457V     79.19mV    2.698V
1.89ns    2.498V     235.1mV    2.699V
2.4ns     2.499V     2.144V     2.699V
3.075ns   2.499V     2.296V     2.7V
238.2ns   2.5V       2.3V       2.7V
[Falling Waveform]
| AOUT_4MA_25
R_fixture =   1000
C_fixture =   0
L_fixture =   0
V_fixture =   0
V_fixture_min = 0
V_fixture_max = 0
|   Time   V(typ)   V(min)   V(max)
0s        2.45V      2.23V      2.665V
590ps     2.45V      2.23V      2.649V
700ps     2.45V      2.23V      2.22V
890ps     2.452V     2.23V      206.4mV
1.325ns   2.295V     2.229V     2.412mV
1.785ns   290.3mV    2.23V      1.052mV
2.69ns    3.516mV    2.234V     452.3uV
3.745ns   752uV      261.4mV    193.3uV
5.115ns   262uV      6.218mV    71.58uV
238.2ns   25.79nV    63.63nV    8.601nV
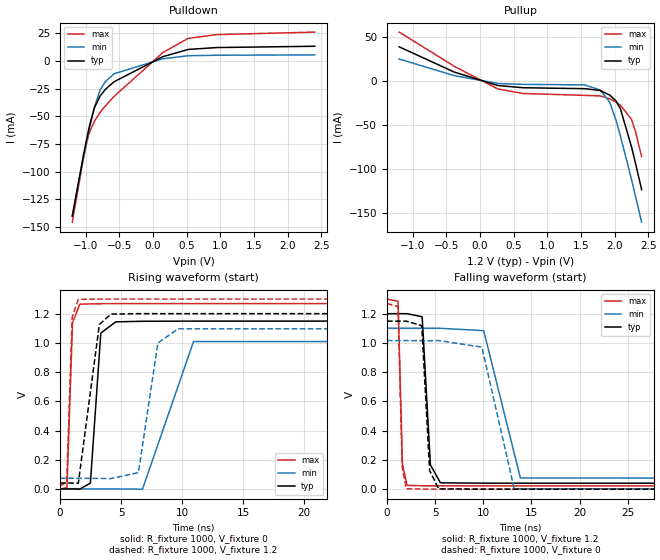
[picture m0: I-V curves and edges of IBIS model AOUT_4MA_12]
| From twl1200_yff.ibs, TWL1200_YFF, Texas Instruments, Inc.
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[Model]   AOUT_4MA_12
Model_type  Output
Vref =   1.2
Rref =   1M
Cref =   15p
Vmeas =   0.6
| variable   typ   min   max
C_comp   3.72pF   2.69pF   4.46pF
| C_pullup   3.80pF   2.69pF   4.46pF
| C_pulldown   3.64pF   2.93pF   4.24pF
[Temperature Range]   40   100   -40
| Ambient temperature   25   85   -40
[Voltage range]   1.2   1.1   1.3
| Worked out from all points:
|   slope of the pulldown table from 0 to 0.18 V, typ, clamps not added: 38.2 ohm
|   slope of the pullup table from 0 to 0.18 V, typ, clamps not added: 50.1 ohm
|   rising waveform, R_fixture 1000, V_fixture 0: 20-80 % time 453ps typ, 946ps min, 248ps max; typ from 0 V to 1.15 V
|   falling waveform, R_fixture 1000, V_fixture 1.2: 20-80 % time 450ps typ, 945ps min, 238ps max; typ from 1.2 V to 0.041 V
|   rising waveform, R_fixture 1000, V_fixture 1.2: 20-80 % time 432ps typ, 876ps min, 242ps max; typ from 0.041 V to 1.2 V
|   falling waveform, R_fixture 1000, V_fixture 0: 20-80 % time 434ps typ, 891ps min, 233ps max; typ from 1.15 V to 0 V
[Pulldown]
| AOUT_4MA_12
|   Voltage   I(typ)   I(min)   I(max)
-1.2V     -140.4mA   -139.7mA   -145.7mA
-1.04V    -87.09mA   -88.67mA   -89.86mA
-980mV    -68.77mA   -70.71mA   -72.36mA
-940mV    -57.64mA   -59.36mA   -63.67mA
-870mV    -42.03mA   -41.52mA   -54.37mA
-785mV    -31.56mA   -25.97mA   -46.28mA
-710mV    -25.74mA   -18.72mA   -40.72mA
-580mV    -18.83mA   -11.58mA   -32.09mA
145mV     3.881mA    1.935mA    7.564mA
520mV     10.38mA    4.699mA    20.37mA
945mV     12.09mA    5.128mA    23.77mA
2.4V      13.26mA    5.469mA    26.06mA
[Pullup]
| AOUT_4MA_12
|   Voltage   I(typ)   I(min)   I(max)
-1.2V     39.25mA    25.31mA    56.04mA
-380mV    10.39mA    6.347mA    16.94mA
265mV     -4.877mA   -2.587mA   -8.855mA
640mV     -7.444mA   -3.597mA   -13.98mA
1.555V    -8.502mA   -4.171mA   -16.16mA
1.785V    -10.59mA   -10mA      -16.78mA
1.925V    -15.77mA   -23.73mA   -19.95mA
2.02V     -22.5mA    -44.61mA   -23.89mA
2.085V    -31.42mA   -62.29mA   -27.31mA
2.25V     -74.88mA   -112.3mA   -43.52mA
2.31V     -93.88mA   -131.5mA   -57.69mA
2.4V      -123.6mA   -160.8mA   -85.85mA
[Ramp]
| AOUT_4MA_12
| variable   typ   min   max
dV/dt_r   0.70/4.67E-10   0.62/9.63E-10   0.77/2.58E-10
dV/dt_f   0.70/4.58E-10   0.62/9.54E-10   0.77/2.51E-10
R_load = 1000
[Rising Waveform]
| AOUT_4MA_12
R_fixture =   1000
C_fixture =   0
L_fixture =   0
V_fixture =   0
V_fixture_min = 0
V_fixture_max = 0
|   Time   V(typ)   V(min)   V(max)
0s        7.788nV    49.21nV    600.2pV
555ps     124.1uV    393.5nV    7.85mV
1.015ns   516.8uV    -916.2nV   1.138V
1.61ns    -1.196mV   -15.71uV   1.265V
2.48ns    40.39mV    45.04uV    1.267V
3.335ns   1.067V     514.3uV    1.268V
4.56ns    1.144V     155.3uV    1.269V
6.755ns   1.148V     -1.352mV   1.269V
10.94ns   1.149V     1.009V     1.269V
237.3ns   1.149V     1.016V     1.269V
[Falling Waveform]
| AOUT_4MA_12
R_fixture =   1000
C_fixture =   0
L_fixture =   0
V_fixture =   1.2
V_fixture_min = 1.1
V_fixture_max = 1.3
|   Time   V(typ)   V(min)   V(max)
0s        1.2V       1.1V       1.3V
1.145ns   1.2V       1.1V       1.285V
1.6ns     1.2V       1.1V       172.6mV
2.08ns    1.2V       1.1V       26.12mV
3.65ns    1.179V     1.1V       23.3mV
4.505ns   166mV      1.1V       23.05mV
5.55ns    43.41mV    1.1V       22.93mV
10.04ns   41.04mV    1.084V     22.82mV
13.85ns   40.83mV    76.32mV    22.82mV
237.3ns   40.8mV     73mV       22.82mV
[Rising Waveform]
| AOUT_4MA_12
R_fixture =   1000
C_fixture =   0
L_fixture =   0
V_fixture =   1.2
V_fixture_min = 1.1
V_fixture_max = 1.3
|   Time   V(typ)   V(min)   V(max)
0s        40.8mV     73mV       22.82mV
540ps     40.91mV    73mV       44.03mV
985ps     40.67mV    73mV       1.177V
1.49ns    39.38mV    73mV       1.298V
3.215ns   1.126V     72.55mV    1.3V
4.165ns   1.197V     70.88mV    1.3V
6.42ns    1.2V       112mV      1.3V
8.015ns   1.2V       998.9mV    1.3V
9.67ns    1.2V       1.096V     1.3V
237.3ns   1.2V       1.1V       1.3V
[Falling Waveform]
| AOUT_4MA_12
R_fixture =   1000
C_fixture =   0
L_fixture =   0
V_fixture =   0
V_fixture_min = 0
V_fixture_max = 0
|   Time   V(typ)   V(min)   V(max)
0s        1.149V     1.016V     1.269V
1.14ns    1.149V     1.016V     1.249V
1.575ns   1.149V     1.016V     152mV
2ns       1.149V     1.016V     3.044mV
3.61ns    1.118V     1.015V     401.9uV
4.425ns   127mV      1.015V     213uV
5.37ns    1.999mV    1.016V     109.3uV
9.85ns    205.5uV    971.5mV    6.051uV
13.21ns   27.12uV    2.402mV    727.5nV
237.3ns   7.353nV    48.42nV    2.977nV
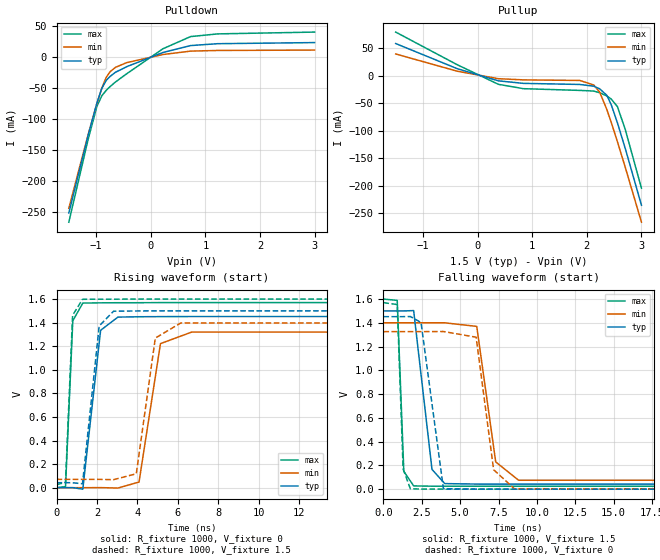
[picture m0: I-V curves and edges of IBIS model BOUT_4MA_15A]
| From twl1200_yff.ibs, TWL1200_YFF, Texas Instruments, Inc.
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[Model]   BOUT_4MA_15A
Model_type  Output
Vref =   1.5
Rref =   1M
Cref =   15p
Vmeas =   0.75
| variable   typ   min   max
C_comp   3.67pF   2.70pF   4.53pF
| C_pullup   3.83pF   2.70pF   4.53pF
| C_pulldown   3.51pF   2.90pF   4.04pF
[Temperature Range]   40   100   -40
| Ambient temperature   25   85   -40
[Voltage range]   1.5   1.4   1.6
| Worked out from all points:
|   slope of the pulldown table from 0 to 0.225 V, typ, clamps not added: 30.9 ohm
|   slope of the pullup table from 0 to 0.225 V, typ, clamps not added: 36.5 ohm
|   rising waveform, R_fixture 1000, V_fixture 0: 20-80 % time 317ps typ, 569ps min, 195ps max; typ from 0 V to 1.45 V
|   falling waveform, R_fixture 1000, V_fixture 1.5: 20-80 % time 354ps typ, 658ps min, 202ps max; typ from 1.5 V to 0.042 V
|   rising waveform, R_fixture 1000, V_fixture 1.5: 20-80 % time 304ps typ, 529ps min, 190ps max; typ from 0.042 V to 1.5 V
|   falling waveform, R_fixture 1000, V_fixture 0: 20-80 % time 345ps typ, 627ps min, 195ps max; typ from 1.45 V to 0 V
[Pulldown]
| BOUT_4MA_15A
|   Voltage   I(typ)   I(min)   I(max)
-1.5V     -252.3mA   -244.7mA   -267.1mA
-1.145V   -126.2mA   -125.1mA   -132.8mA
-985mV    -74.27mA   -75.09mA   -79.67mA
-895mV    -50.61mA   -50.23mA   -62.71mA
-815mV    -37.93mA   -32.99mA   -53.98mA
-745mV    -31.52mA   -23.89mA   -47.92mA
-645mV    -24.72mA   -16.76mA   -40.45mA
-440mV    -15.71mA   -9.184mA   -27.14mA
225mV     7.289mA    3.957mA    13.31mA
730mV     18.4mA     9.446mA    32.94mA
1.225V    21.44mA    10.49mA    37.29mA
3V        23.24mA    11.13mA    40.2mA
[Pullup]
| BOUT_4MA_15A
|   Voltage   I(typ)   I(min)   I(max)
-1.5V     58.43mA    39.5mA     79.24mA
-375mV    12.81mA    8.188mA    20.01mA
380mV     -9.351mA   -5.433mA   -15.65mA
840mV     -13.96mA   -7.606mA   -23.59mA
1.87V     -15.9mA    -8.639mA   -26.73mA
2.125V    -19.05mA   -16.81mA   -27.91mA
2.235V    -23.83mA   -29.96mA   -30.95mA
2.365V    -35.58mA   -61.14mA   -36.82mA
2.445V    -52.34mA   -84.36mA   -42.29mA
2.56V     -85.59mA   -120mA     -56.15mA
2.705V    -132.9mA   -167mA     -98.26mA
3V        -235.4mA   -266.2mA   -204.5mA
[Ramp]
| BOUT_4MA_15A
| variable   typ   min   max
dV/dt_r   0.88/3.26E-10   0.81/5.82E-10   0.95/1.99E-10
dV/dt_f   0.88/3.63E-10   0.80/6.65E-10   0.95/2.20E-10
R_load = 1000
[Rising Waveform]
| BOUT_4MA_15A
R_fixture =   1000
C_fixture =   0
L_fixture =   0
V_fixture =   0
V_fixture_min = 0
V_fixture_max = 0
|   Time   V(typ)   V(min)   V(max)
0s        7.508nV    41.43nV    653.6pV
445ps     589.1uV    -193.6nV   9.564mV
805ps     504uV      -12.59uV   1.416V
1.3ns     -12.44mV   -36.41uV   1.566V
2.18ns    1.335V     720.3uV    1.568V
3.035ns   1.447V     -2.937mV   1.569V
4.08ns    1.45V      47.92mV    1.569V
5.14ns    1.451V     1.222V     1.57V
6.685ns   1.452V     1.32V      1.57V
237.8ns   1.452V     1.326V     1.57V
[Falling Waveform]
| BOUT_4MA_15A
R_fixture =   1000
C_fixture =   0
L_fixture =   0
V_fixture =   1.5
V_fixture_min = 1.4
V_fixture_max = 1.6
|   Time   V(typ)   V(min)   V(max)
0s        1.5V       1.4V       1.6V
900ps     1.5V       1.4V       1.589V
1.33ns    1.5V       1.4V       150.3mV
1.97ns    1.503V     1.4V       27.48mV
3.165ns   166.3mV    1.4V       25.09mV
3.995ns   46.84mV    1.4V       24.85mV
6.08ns    42.89mV    1.37V      24.67mV
7.315ns   42.44mV    229.4mV    24.64mV
8.805ns   42.27mV    75.25mV    24.62mV
237.8ns   42.16mV    70.83mV    24.62mV
[Rising Waveform]
| BOUT_4MA_15A
R_fixture =   1000
C_fixture =   0
L_fixture =   0
V_fixture =   1.5
V_fixture_min = 1.4
V_fixture_max = 1.6
|   Time   V(typ)   V(min)   V(max)
0s        42.16mV    70.83mV    24.62mV
445ps     42.7mV     70.83mV    46.5mV
795ps     42mV       70.82mV    1.462V
1.285ns   33.4mV     70.83mV    1.598V
2.11ns    1.372V     70.64mV    1.599V
2.82ns    1.497V     68.24mV    1.599V
3.945ns   1.499V     118.3mV    1.6V
4.885ns   1.5V       1.269V     1.6V
6.14ns    1.5V       1.397V     1.6V
237.8ns   1.5V       1.4V       1.6V
[Falling Waveform]
| BOUT_4MA_15A
R_fixture =   1000
C_fixture =   0
L_fixture =   0
V_fixture =   0
V_fixture_min = 0
V_fixture_max = 0
|   Time   V(typ)   V(min)   V(max)
0s        1.452V     1.326V     1.57V
900ps     1.452V     1.326V     1.554V
1.285ns   1.452V     1.326V     169.9mV
1.755ns   1.453V     1.326V     3.309mV
2.45ns    1.403V     1.326V     800.5uV
3.91ns    4.027mV    1.327V     222.5uV
6.04ns    602.9uV    1.279V     50.03uV
7.18ns    258.3uV    163.8mV    23.69uV
8.53ns    108.2uV    3.57mV     9.904uV
237.8ns   10.61nV    42.62nV    7.498nV
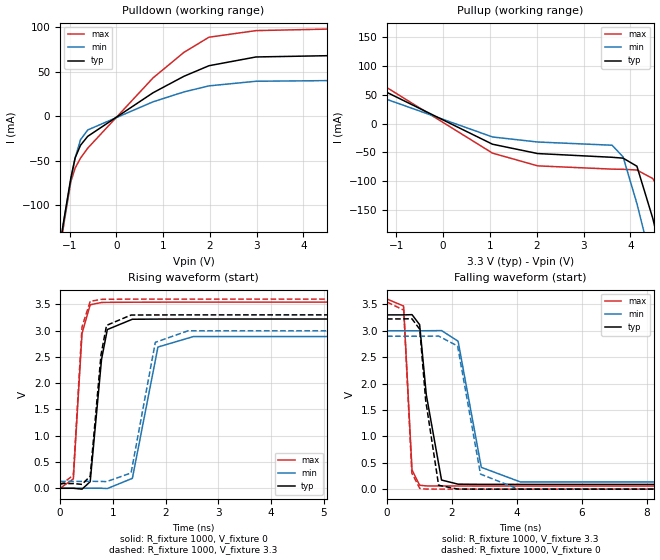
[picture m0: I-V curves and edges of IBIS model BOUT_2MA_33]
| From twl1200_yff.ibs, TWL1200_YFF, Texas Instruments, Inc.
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[Model]   BOUT_2MA_33
Model_type  Output
Vref =   3.3
Rref =   1M
Cref =   15p
Vmeas =   1.65
| variable   typ   min   max
C_comp   2.80pF   2.19pF   3.83pF
| C_pullup   2.97pF   2.20pF   3.83pF
| C_pulldown   2.64pF   2.19pF   3.03pF
[Temperature Range]   40   100   -40
| Ambient temperature   25   85   -40
[Voltage range]   3.3   3   3.6
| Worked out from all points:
|   slope of the pulldown table from 0 to 0.495 V, typ, clamps not added: 29 ohm
|   slope of the pullup table from 0 to 0.495 V, typ, clamps not added: 25.9 ohm
|   rising waveform, R_fixture 1000, V_fixture 0: 20-80 % time 161ps typ, 263ps min, 110ps max; typ from 0 V to 3.22 V
|   falling waveform, R_fixture 1000, V_fixture 3.3: 20-80 % time 265ps typ, 415ps min, 131ps max; typ from 3.3 V to 0.09 V
|   rising waveform, R_fixture 1000, V_fixture 3.3: 20-80 % time 157ps typ, 249ps min, 107ps max; typ from 0.09 V to 3.3 V
|   falling waveform, R_fixture 1000, V_fixture 0: 20-80 % time 229ps typ, 405ps min, 122ps max; typ from 3.22 V to 0 V
[Pulldown]
| BOUT_2MA_33
|   Voltage   I(typ)   I(min)   I(max)
-3.3V     -920.6mA   -883.6mA   -974mA
-1.155V   -128.8mA   -128.9mA   -134mA
-1.12V    -116.9mA   -117.6mA   -121.3mA
-970mV    -69.28mA   -71.36mA   -73.43mA
-880mV    -47.07mA   -47.2mA    -58.57mA
-765mV    -32.82mA   -26.63mA   -47.34mA
-610mV    -22.73mA   -15.58mA   -36.05mA
785mV     26.3mA     16.1mA     43mA
1.445V    44.83mA    27.22mA    71.78mA
1.98V     56.73mA    34.04mA    88.83mA
2.985V    66.59mA    39.23mA    96.27mA
6.6V      69.98mA    40.97mA    100.3mA
[Pullup]
| BOUT_2MA_33
|   Voltage   I(typ)   I(min)   I(max)
-3.3V     137.9mA    102.7mA    168.2mA
1.055V    -35.8mA    -23.2mA    -51.29mA
2.02V     -51.99mA   -31.94mA   -73.36mA
3.61V     -58.47mA   -37.53mA   -79.02mA
3.845V    -59.95mA   -57.8mA    -79.34mA
4.14V     -73.99mA   -138.8mA   -80.56mA
4.48V     -164.7mA   -249.5mA   -95.43mA
4.58V     -198.1mA   -283mA     -109.8mA
4.715V    -244.3mA   -328.8mA   -149.7mA
4.97V     -333.6mA   -416.2mA   -239.1mA
5.07V     -369mA     -450.8mA   -275.5mA
6.6V      -925.5mA   -989.6mA   -852.6mA
[Ramp]
| BOUT_2MA_33
| variable   typ   min   max
dV/dt_r   1.95/1.69E-10   1.75/2.71E-10   2.14/1.12E-10
dV/dt_f   1.93/2.71E-10   1.73/4.24E-10   2.13/1.42E-10
R_load = 1000
[Rising Waveform]
| BOUT_2MA_33
R_fixture =   1000
C_fixture =   0
L_fixture =   0
V_fixture =   0
V_fixture_min = 0
V_fixture_max = 0
|   Time   V(typ)   V(min)   V(max)
0s        12.11nV    39.49nV    1.712nV
250ps     627.6uV    -45.46uV   177.8mV
415ps     -17.07mV   70.01uV    2.947V
570ps     125.5mV    1.195mV    3.491V
785ps     2.452V     178.2uV    3.535V
895ps     3.02V      -5.271mV   3.537V
1.37ns    3.216V     188.9mV    3.54V
1.855ns   3.219V     2.687V     3.541V
2.53ns    3.22V      2.887V     3.542V
238.2ns   3.223V     2.896V     3.543V
[Falling Waveform]
| BOUT_2MA_33
R_fixture =   1000
C_fixture =   0
L_fixture =   0
V_fixture =   3.3
V_fixture_min = 3
V_fixture_max = 3.6
|   Time   V(typ)   V(min)   V(max)
0s        3.3V       3V         3.6V
510ps     3.3V       3V         3.469V
770ps     3.305V     3V         364.9mV
1.005ns   3.115V     2.999V     74.67mV
1.21ns    1.788V     3V         61.49mV
1.68ns    172.8mV    3.003V     60.49mV
2.19ns    94.54mV    2.802V     59.99mV
2.905ns   91.09mV    413.3mV    59.64mV
4.11ns    90.26mV    136.8mV    59.41mV
238.2ns   89.85mV    131mV      59.28mV
[Rising Waveform]
| BOUT_2MA_33
R_fixture =   1000
C_fixture =   0
L_fixture =   0
V_fixture =   3.3
V_fixture_min = 3
V_fixture_max = 3.6
|   Time   V(typ)   V(min)   V(max)
0s        89.85mV    131mV      59.28mV
250ps     90.18mV    131mV      247.2mV
415ps     73.83mV    131.1mV    3.071V
570ps     230.4mV    132.1mV    3.557V
775ps     2.54V      130.8mV    3.594V
880ps     3.099V     125.8mV    3.596V
1.345ns   3.296V     291.1mV    3.599V
1.805ns   3.298V     2.776V     3.599V
2.425ns   3.299V     2.996V     3.599V
238.2ns   3.3V       3V         3.6V
[Falling Waveform]
| BOUT_2MA_33
R_fixture =   1000
C_fixture =   0
L_fixture =   0
V_fixture =   0
V_fixture_min = 0
V_fixture_max = 0
|   Time   V(typ)   V(min)   V(max)
0s        3.223V     2.896V     3.543V
515ps     3.224V     2.896V     3.391V
765ps     3.228V     2.896V     304mV
1.01ns    3.027V     2.895V     13.47mV
1.19ns    1.688V     2.896V     2.14mV
1.59ns    73.65mV    2.899V     1.131mV
2.175ns   2.419mV    2.711V     632.6uV
2.88ns    943.3uV    285.5mV    334.3uV
4.035ns   348.1uV    5.127mV    133.9uV
238.2ns   112.7nV    78.88nV    11.64nV
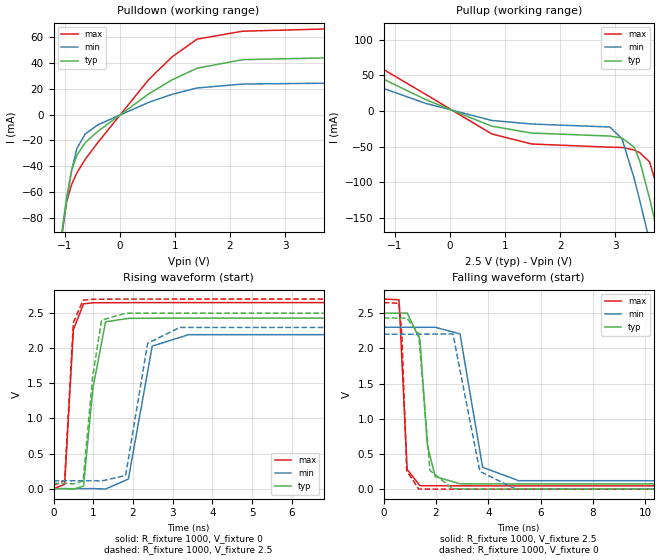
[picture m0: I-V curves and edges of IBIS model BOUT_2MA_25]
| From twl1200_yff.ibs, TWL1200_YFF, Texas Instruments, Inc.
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[Model]   BOUT_2MA_25
Model_type  Output
Vref =   2.5
Rref =   1M
Cref =   15p
Vmeas =   1.25
| variable   typ   min   max
C_comp   2.97pF   2.30pF   3.93pF
| C_pullup   3.15pF   2.30pF   3.93pF
| C_pulldown   2.80pF   2.37pF   3.10pF
[Temperature Range]   40   100   -40
| Ambient temperature   25   85   -40
[Voltage range]   2.5   2.3   2.7
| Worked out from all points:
|   slope of the pulldown table from 0 to 0.375 V, typ, clamps not added: 31.9 ohm
|   slope of the pullup table from 0 to 0.375 V, typ, clamps not added: 31.2 ohm
|   rising waveform, R_fixture 1000, V_fixture 0: 20-80 % time 212ps typ, 335ps min, 131ps max; typ from 0 V to 2.43 V
|   falling waveform, R_fixture 1000, V_fixture 2.5: 20-80 % time 279ps typ, 459ps min, 133ps max; typ from 2.5 V to 0.074 V
|   rising waveform, R_fixture 1000, V_fixture 2.5: 20-80 % time 201ps typ, 312ps min, 127ps max; typ from 0.074 V to 2.5 V
|   falling waveform, R_fixture 1000, V_fixture 0: 20-80 % time 268ps typ, 442ps min, 129ps max; typ from 2.43 V to 0 V
[Pulldown]
| BOUT_2MA_25
|   Voltage   I(typ)   I(min)   I(max)
-2.5V     -613.9mA   -592.1mA   -647mA
-1.08V    -100.5mA   -102.5mA   -102.8mA
-960mV    -63.69mA   -66.41mA   -67.21mA
-870mV    -42.73mA   -42.95mA   -53.95mA
-775mV    -31.45mA   -26.1mA    -45.09mA
-625mV    -21.67mA   -14.95mA   -34.66mA
-395mV    -12.91mA   -7.871mA   -21.58mA
520mV     15.96mA    9.438mA    26.92mA
950mV     27.04mA    15.82mA    44.88mA
1.405V    36.11mA    20.73mA    58.68mA
2.23V     42.74mA    23.81mA    64.84mA
5V        45.24mA    24.96mA    68.04mA
[Pullup]
| BOUT_2MA_25
|   Voltage   I(typ)   I(min)   I(max)
-2.5V     93.34mA    67.24mA    117.6mA
-445mV    16.17mA    10.79mA    23.59mA
760mV     -21.43mA   -13.38mA   -32.31mA
1.485V    -31.06mA   -18.38mA   -46.45mA
2.905V    -35.31mA   -22.63mA   -50.98mA
3.125V    -38.07mA   -39.36mA   -51.31mA
3.345V    -50.98mA   -94.93mA   -54.88mA
3.445V    -70.08mA   -125.5mA   -58.62mA
3.625V    -123.2mA   -183.2mA   -71.69mA
3.815V    -186.2mA   -246.2mA   -121.4mA
4.015V    -255.2mA   -313.7mA   -190.9mA
5V        -608.3mA   -655.6mA   -557.7mA
[Ramp]
| BOUT_2MA_25
| variable   typ   min   max
dV/dt_r   1.47/2.28E-10   1.33/3.44E-10   1.60/1.35E-10
dV/dt_f   1.46/2.84E-10   1.32/4.64E-10   1.59/1.35E-10
R_load = 1000
[Rising Waveform]
| BOUT_2MA_25
R_fixture =   1000
C_fixture =   0
L_fixture =   0
V_fixture =   0
V_fixture_min = 0
V_fixture_max = 0
|   Time   V(typ)   V(min)   V(max)
0s        9.488nV    37.44nV    1.264nV
280ps     1.508mV    -14.75uV   62.22mV
500ps     -6.583mV   -53.87uV   2.264V
755ps     36.97mV    667.6uV    2.632V
990ps     1.425V     1.77mV     2.647V
1.31ns    2.376V     -4.813mV   2.648V
1.885ns   2.425V     137.9mV    2.649V
2.485ns   2.427V     2.03V      2.65V
3.4ns     2.429V     2.193V     2.65V
238.2ns   2.431V     2.201V     2.651V
[Falling Waveform]
| BOUT_2MA_25
R_fixture =   1000
C_fixture =   0
L_fixture =   0
V_fixture =   2.5
V_fixture_min = 2.3
V_fixture_max = 2.7
|   Time   V(typ)   V(min)   V(max)
0s        2.5V       2.3V       2.7V
585ps     2.499V     2.3V       2.69V
895ps     2.502V     2.3V       281.1mV
1.385ns   2.122V     2.299V     49.55mV
1.665ns   632.4mV    2.299V     48.59mV
1.965ns   179.6mV    2.3V       48.21mV
2.915ns   77.01mV    2.205V     47.58mV
3.78ns    75.04mV    310.7mV    47.36mV
5.16ns    74.43mV    119.9mV    47.23mV
238.2ns   74.14mV    112.9mV    47.16mV
[Rising Waveform]
| BOUT_2MA_25
R_fixture =   1000
C_fixture =   0
L_fixture =   0
V_fixture =   2.5
V_fixture_min = 2.3
V_fixture_max = 2.7
|   Time   V(typ)   V(min)   V(max)
0s        74.14mV    112.9mV    47.16mV
280ps     75.43mV    112.9mV    117.5mV
500ps     67.54mV    112.9mV    2.368V
745ps     108.7mV    113.5mV    2.684V
985ps     1.595V     114mV      2.697V
1.21ns    2.4V       110mV      2.698V
1.815ns   2.498V     187.1mV    2.699V
2.37ns    2.499V     2.07V      2.699V
3.18ns    2.499V     2.296V     2.7V
238.2ns   2.5V       2.3V       2.7V
[Falling Waveform]
| BOUT_2MA_25
R_fixture =   1000
C_fixture =   0
L_fixture =   0
V_fixture =   0
V_fixture_min = 0
V_fixture_max = 0
|   Time   V(typ)   V(min)   V(max)
0s        2.431V     2.201V     2.651V
585ps     2.43V      2.201V     2.639V
695ps     2.431V     2.201V     2.182V
880ps     2.432V     2.201V     261.7mV
1.335ns   2.209V     2.201V     2.497mV
1.765ns   266.9mV    2.202V     1.064mV
2.645ns   3.475mV    2.204V     465uV
3.675ns   776.6uV    251.6mV    201uV
5.02ns    274.7uV    6.423mV    75.71uV
238.2ns   32.46nV    73.06nV    11.84nV
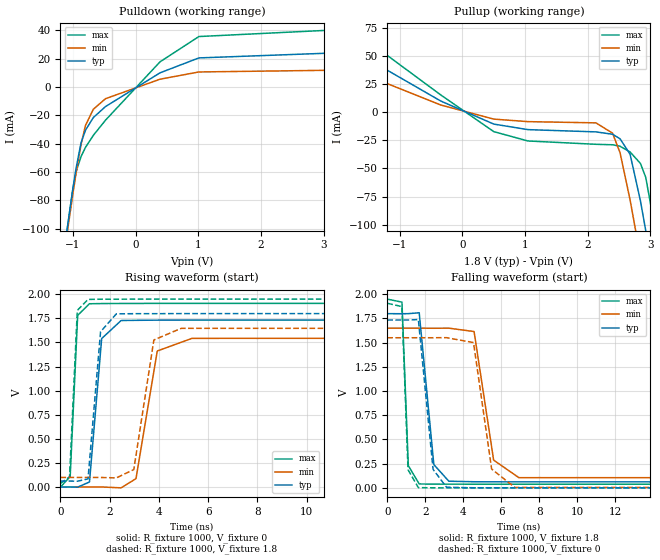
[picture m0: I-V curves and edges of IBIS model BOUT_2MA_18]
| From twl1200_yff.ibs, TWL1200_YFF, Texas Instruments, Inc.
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[Model]   BOUT_2MA_18
Model_type  Output
Vref =   1.8
Rref =   1M
Cref =   15p
Vmeas =   0.9
| variable   typ   min   max
C_comp   3.13pF   2.42pF   3.95pF
| C_pullup   3.28pF   2.42pF   3.95pF
| C_pulldown   2.98pF   2.58pF   3.30pF
[Temperature Range]   40   100   -40
| Ambient temperature   25   85   -40
[Voltage range]   1.8   1.65   1.95
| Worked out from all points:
|   slope of the pulldown table from 0 to 0.27 V, typ, clamps not added: 37.6 ohm
|   slope of the pullup table from 0 to 0.27 V, typ, clamps not added: 41.7 ohm
|   rising waveform, R_fixture 1000, V_fixture 0: 20-80 % time 292ps typ, 503ps min, 163ps max; typ from 0 V to 1.73 V
|   falling waveform, R_fixture 1000, V_fixture 1.8: 20-80 % time 313ps typ, 559ps min, 170ps max; typ from 1.8 V to 0.062 V
|   rising waveform, R_fixture 1000, V_fixture 1.8: 20-80 % time 275ps typ, 455ps min, 156ps max; typ from 0.062 V to 1.8 V
|   falling waveform, R_fixture 1000, V_fixture 0: 20-80 % time 305ps typ, 534ps min, 163ps max; typ from 1.73 V to 0 V
[Pulldown]
| BOUT_2MA_18
|   Voltage   I(typ)   I(min)   I(max)
-1.8V     -349.1mA   -340.8mA   -364.2mA
-1.09V    -99.54mA   -102.5mA   -100mA
-1.075V   -94.69mA   -97.84mA   -94.96mA
-1V       -71.37mA   -75.11mA   -71.66mA
-950mV    -57.18mA   -60.78mA   -59.73mA
-870mV    -39.25mA   -40.36mA   -49.01mA
-800mV    -30.47mA   -27.08mA   -42.61mA
-675mV    -21.56mA   -15.69mA   -34.14mA
-480mV    -13.79mA   -8.218mA   -23.39mA
390mV     10.04mA    5.538mA    17.83mA
1.01V     20.57mA    10.65mA    35.68mA
3.6V      24.79mA    12.14mA    41.25mA
[Pullup]
| BOUT_2MA_18
|   Voltage   I(typ)   I(min)   I(max)
-1.8V     56.5mA     38.65mA    75.07mA
-345mV    9.821mA    6.33mA     15.22mA
500mV     -10.61mA   -6.182mA   -17.34mA
1.045V    -15.53mA   -8.426mA   -25.61mA
2.13V     -17.53mA   -9.514mA   -28.57mA
2.395V    -19.64mA   -18.67mA   -28.98mA
2.515V    -23.66mA   -36.03mA   -30.31mA
2.675V    -37.4mA    -77.95mA   -35.36mA
2.84V     -78.74mA   -128.6mA   -45.55mA
2.925V    -105.2mA   -155.8mA   -57.93mA
3.135V    -175mA     -225mA     -122.6mA
3.6V      -337.7mA   -382.9mA   -291mA
[Ramp]
| BOUT_2MA_18
| variable   typ   min   max
dV/dt_r   1.05/2.95E-10   0.94/5.15E-10   1.15/1.71E-10
dV/dt_f   1.05/3.17E-10   0.94/5.67E-10   1.15/1.75E-10
R_load = 1000
[Rising Waveform]
| BOUT_2MA_18
R_fixture =   1000
C_fixture =   0
L_fixture =   0
V_fixture =   0
V_fixture_min = 0
V_fixture_max = 0
|   Time   V(typ)   V(min)   V(max)
0s        8.063nV    38.78nV    973pV
395ps     867.7uV    -1.342uV   108.4mV
700ps     -1.146mV   -26.72uV   1.782V
1.18ns    52.99mV    174.9uV    1.902V
1.675ns   1.541V     1.002mV    1.904V
2.465ns   1.728V     -8.292mV   1.905V
3.07ns    1.73V      87.77mV    1.905V
3.935ns   1.732V     1.412V     1.906V
5.345ns   1.733V     1.543V     1.906V
238ns     1.734V     1.551V     1.907V
[Falling Waveform]
| BOUT_2MA_18
R_fixture =   1000
C_fixture =   0
L_fixture =   0
V_fixture =   1.8
V_fixture_min = 1.65
V_fixture_max = 1.95
|   Time   V(typ)   V(min)   V(max)
0s        1.8V       1.65V      1.95V
770ps     1.799V     1.65V      1.919V
1.105ns   1.8V       1.65V      229.8mV
1.68ns    1.809V     1.65V      40.38mV
2.45ns    240.7mV    1.649V     38.52mV
3.24ns    68.68mV    1.65V      38.11mV
4.57ns    63.1mV     1.615V     37.87mV
5.6ns     62.4mV     286.7mV    37.8mV
6.93ns    62.12mV    105.4mV    37.76mV
238ns     61.95mV    99.65mV    37.74mV
[Rising Waveform]
| BOUT_2MA_18
R_fixture =   1000
C_fixture =   0
L_fixture =   0
V_fixture =   1.8
V_fixture_min = 1.65
V_fixture_max = 1.95
|   Time   V(typ)   V(min)   V(max)
0s        61.95mV    99.65mV    37.74mV
370ps     62.52mV    99.65mV    106.1mV
685ps     60.36mV    99.64mV    1.833V
1.12ns    84.77mV    99.76mV    1.947V
1.63ns    1.612V     99.61mV    1.949V
2.27ns    1.797V     95.04mV    1.949V
2.98ns    1.799V     181.7mV    1.95V
3.795ns   1.799V     1.526V     1.95V
4.905ns   1.8V       1.647V     1.95V
238ns     1.8V       1.65V      1.95V
[Falling Waveform]
| BOUT_2MA_18
R_fixture =   1000
C_fixture =   0
L_fixture =   0
V_fixture =   0
V_fixture_min = 0
V_fixture_max = 0
|   Time   V(typ)   V(min)   V(max)
0s        1.734V     1.551V     1.907V
770ps     1.734V     1.551V     1.873V
1.09ns    1.734V     1.551V     187.3mV
1.635ns   1.739V     1.551V     2.19mV
2.41ns    191.4mV    1.551V     640uV
3.12ns    6.149mV    1.552V     341.5uV
4.54ns    884.5uV    1.501V     115.2uV
5.495ns   399.7uV    194.4mV    59.52uV
6.715ns   173uV      4.62mV     26.46uV
238ns     22.34nV    45.79nV    12.21nV
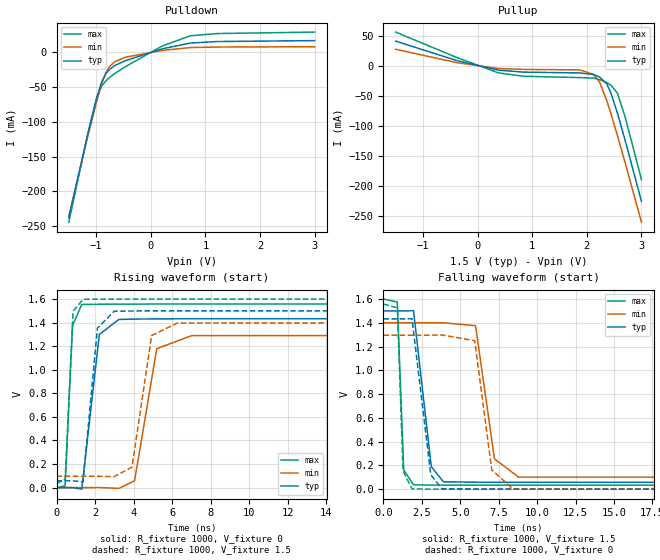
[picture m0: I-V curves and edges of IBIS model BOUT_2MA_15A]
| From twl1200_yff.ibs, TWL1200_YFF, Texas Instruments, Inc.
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[Model]   BOUT_2MA_15A
Model_type  Output
Vref =   1.5
Rref =   1M
Cref =   15p
Vmeas =   0.75
| variable   typ   min   max
C_comp   3.19pF   2.49pF   3.92pF
| C_pullup   3.31pF   2.49pF   3.92pF
| C_pulldown   3.07pF   2.68pF   3.38pF
[Temperature Range]   40   100   -40
| Ambient temperature   25   85   -40
[Voltage range]   1.5   1.4   1.6
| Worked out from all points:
|   slope of the pulldown table from 0 to 0.225 V, typ, clamps not added: 42.7 ohm
|   slope of the pullup table from 0 to 0.225 V, typ, clamps not added: 51.2 ohm
|   rising waveform, R_fixture 1000, V_fixture 0: 20-80 % time 365ps typ, 658ps min, 223ps max; typ from 0 V to 1.43 V
|   falling waveform, R_fixture 1000, V_fixture 1.5: 20-80 % time 355ps typ, 663ps min, 203ps max; typ from 1.5 V to 0.058 V
|   rising waveform, R_fixture 1000, V_fixture 1.5: 20-80 % time 342ps typ, 580ps min, 213ps max; typ from 0.058 V to 1.5 V
|   falling waveform, R_fixture 1000, V_fixture 0: 20-80 % time 343ps typ, 623ps min, 196ps max; typ from 1.43 V to 0 V
[Pulldown]
| BOUT_2MA_15A
|   Voltage   I(typ)   I(min)   I(max)
-1.5V     -237.9mA   -235.7mA   -244.3mA
-1.15V    -116.7mA   -119.8mA   -116.4mA
-985mV    -64.62mA   -69.26mA   -63.78mA
-895mV    -41.83mA   -44.94mA   -48.14mA
-820mV    -30.44mA   -29.03mA   -41.03mA
-755mV    -24.91mA   -20.44mA   -36.25mA
-660mV    -19.09mA   -13.79mA   -30.54mA
-465mV    -12.09mA   -7.122mA   -20.74mA
210mV     4.948mA    2.684mA    9.045mA
725mV     13.24mA    6.787mA    23.72mA
1.22V     15.46mA    7.546mA    26.92mA
3V        16.76mA    8.01mA     29.03mA
[Pullup]
| BOUT_2MA_15A
|   Voltage   I(typ)   I(min)   I(max)
-1.5V     41.81mA    28.18mA    56.83mA
-385mV    9.383mA    5.97mA     14.66mA
380mV     -6.659mA   -3.858mA   -11.17mA
840mV     -9.923mA   -5.388mA   -16.8mA
1.87V     -11.29mA   -6.173mA   -19.03mA
2.12V     -13.84mA   -13.59mA   -19.87mA
2.235V    -18.3mA    -26.77mA   -22.45mA
2.365V    -29.42mA   -57.55mA   -27.39mA
2.445V    -45.76mA   -80.5mA    -32.21mA
2.56V     -78.36mA   -115.7mA   -45.09mA
2.705V    -124.8mA   -162.2mA   -85.89mA
3V        -225.4mA   -260.1mA   -189.3mA
[Ramp]
| BOUT_2MA_15A
| variable   typ   min   max
dV/dt_r   0.87/3.78E-10   0.79/6.68E-10   0.95/2.33E-10
dV/dt_f   0.87/3.66E-10   0.79/6.69E-10   0.95/2.16E-10
R_load = 1000
[Rising Waveform]
| BOUT_2MA_15A
R_fixture =   1000
C_fixture =   0
L_fixture =   0
V_fixture =   0
V_fixture_min = 0
V_fixture_max = 0
|   Time   V(typ)   V(min)   V(max)
0s        7.825nV    41.35nV    863.5pV
445ps     541.6uV    -230.1nV   14.19mV
830ps     428.9uV    -13.46uV   1.373V
1.31ns    -13.02mV   -35.59uV   1.554V
2.225ns   1.3V       678.4uV    1.556V
3.24ns    1.427V     -6.307mV   1.557V
4.055ns   1.43V      58.59mV    1.557V
5.205ns   1.432V     1.179V     1.558V
7.02ns    1.433V     1.29V      1.558V
237.8ns   1.433V     1.296V     1.558V
[Falling Waveform]
| BOUT_2MA_15A
R_fixture =   1000
C_fixture =   0
L_fixture =   0
V_fixture =   1.5
V_fixture_min = 1.4
V_fixture_max = 1.6
|   Time   V(typ)   V(min)   V(max)
0s        1.5V       1.4V       1.6V
905ps     1.5V       1.4V       1.576V
1.32ns    1.5V       1.4V       161.6mV
1.96ns    1.502V     1.4V       36.83mV
3.115ns   189.5mV    1.4V       34.43mV
3.905ns   62.13mV    1.4V       34.17mV
5.995ns   58.72mV    1.376V     33.97mV
7.225ns   58.23mV    255.7mV    33.94mV
8.795ns   58.05mV    101.2mV    33.93mV
237.8ns   57.95mV    97.15mV    33.92mV
[Rising Waveform]
| BOUT_2MA_15A
R_fixture =   1000
C_fixture =   0
L_fixture =   0
V_fixture =   1.5
V_fixture_min = 1.4
V_fixture_max = 1.6
|   Time   V(typ)   V(min)   V(max)
0s        57.95mV    97.15mV    33.92mV
450ps     58.45mV    97.15mV    73.57mV
860ps     57.15mV    97.14mV    1.497V
1.38ns    51.14mV    97.2mV     1.598V
2.125ns   1.353V     96.52mV    1.599V
2.99ns    1.497V     93.2mV     1.599V
3.92ns    1.499V     174.4mV    1.6V
4.94ns    1.5V       1.291V     1.6V
6.285ns   1.5V       1.397V     1.6V
237.8ns   1.5V       1.4V       1.6V
[Falling Waveform]
| BOUT_2MA_15A
R_fixture =   1000
C_fixture =   0
L_fixture =   0
V_fixture =   0
V_fixture_min = 0
V_fixture_max = 0
|   Time   V(typ)   V(min)   V(max)
0s        1.433V     1.296V     1.558V
905ps     1.433V     1.296V     1.526V
1.28ns    1.433V     1.296V     153.3mV
1.86ns    1.435V     1.296V     2.532mV
3.08ns    122.5mV    1.296V     418.9uV
3.8ns     3.244mV    1.298V     233.3uV
5.94ns    594.1uV    1.25V      51.46uV
7.05ns    257.8uV    163.1mV    24.89uV
8.415ns   107.2uV    2.91mV     10.35uV
237.8ns   12.06nV    42.72nV    10.36nV
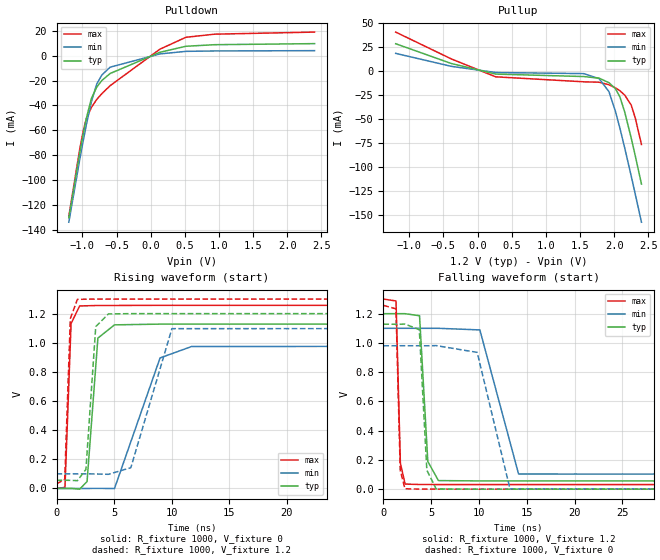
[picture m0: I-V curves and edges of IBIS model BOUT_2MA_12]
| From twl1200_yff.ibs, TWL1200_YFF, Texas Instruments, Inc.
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[Model]   BOUT_2MA_12
Model_type  Output
Vref =   1.2
Rref =   1M
Cref =   15p
Vmeas =   0.6
| variable   typ   min   max
C_comp   3.24pF   2.52pF   3.87pF
| C_pullup   3.31pF   2.52pF   3.87pF
| C_pulldown   3.17pF   2.69pF   3.53pF
[Temperature Range]   40   100   -40
| Ambient temperature   25   85   -40
[Voltage range]   1.2   1.1   1.3
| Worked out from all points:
|   slope of the pulldown table from 0 to 0.18 V, typ, clamps not added: 52.9 ohm
|   slope of the pullup table from 0 to 0.18 V, typ, clamps not added: 69.9 ohm
|   rising waveform, R_fixture 1000, V_fixture 0: 20-80 % time 532ps typ, 1.12ns min, 289ps max; typ from 0 V to 1.13 V
|   falling waveform, R_fixture 1000, V_fixture 1.2: 20-80 % time 464ps typ, 1.01ns min, 243ps max; typ from 1.2 V to 0.056 V
|   rising waveform, R_fixture 1000, V_fixture 1.2: 20-80 % time 480ps typ, 948ps min, 274ps max; typ from 0.056 V to 1.2 V
|   falling waveform, R_fixture 1000, V_fixture 0: 20-80 % time 440ps typ, 918ps min, 235ps max; typ from 1.13 V to 0 V
[Pulldown]
| BOUT_2MA_12
|   Voltage   I(typ)   I(min)   I(max)
-1.2V     -130mA     -133.5mA   -128.8mA
-1.04V    -78.07mA   -83.34mA   -74.92mA
-990mV    -63.13mA   -68.58mA   -60.68mA
-945mV    -50.77mA   -55.94mA   -50.87mA
-870mV    -34.5mA    -37.12mA   -41.66mA
-790mV    -25.18mA   -22.67mA   -35.07mA
-715mV    -19.93mA   -15.52mA   -30.47mA
-595mV    -14.37mA   -9.295mA   -24.13mA
135mV     2.628mA    1.31mA     5.126mA
515mV     7.457mA    3.374mA    14.64mA
935mV     8.709mA    3.688mA    17.14mA
2.4V      9.564mA    3.937mA    18.81mA
[Pullup]
| BOUT_2MA_12
|   Voltage   I(typ)   I(min)   I(max)
-1.2V     28.05mA    18.03mA    40.14mA
-385mV    7.506mA    4.567mA    12.25mA
265mV     -3.472mA   -1.836mA   -6.317mA
1.555V    -6.039mA   -2.994mA   -11.5mA
1.78V     -7.701mA   -8.243mA   -11.93mA
1.925V    -12.45mA   -21.86mA   -14.57mA
2.02V     -18.75mA   -42.47mA   -17.87mA
2.085V    -27.34mA   -59.94mA   -20.79mA
2.155V    -42.93mA   -80.3mA    -25.35mA
2.25V     -69.92mA   -109.4mA   -35.63mA
2.31V     -88.56mA   -128.4mA   -49.27mA
2.4V      -117.7mA   -157.3mA   -76.62mA
[Ramp]
| BOUT_2MA_12
| variable   typ   min   max
dV/dt_r   0.69/5.42E-10   0.60/1.14E-09   0.76/3.03E-10
dV/dt_f   0.69/4.75E-10   0.61/1.01E-09   0.77/2.53E-10
R_load = 1000
[Rising Waveform]
| BOUT_2MA_12
R_fixture =   1000
C_fixture =   0
L_fixture =   0
V_fixture =   0
V_fixture_min = 0
V_fixture_max = 0
|   Time   V(typ)   V(min)   V(max)
0s        8.083nV    48.83nV    793.9pV
735ps     87.98uV    447.6nV    7.366mV
1.265ns   464.9uV    -1.401uV   1.132V
2.01ns    -4.866mV   -21.32uV   1.253V
2.655ns   47.5mV     27.41uV    1.254V
3.595ns   1.032V     482.3uV    1.256V
5.04ns    1.123V     -329.8uV   1.256V
9ns       1.128V     896mV      1.257V
11.75ns   1.128V     974.5mV    1.257V
237.5ns   1.128V     980.8mV    1.257V
[Falling Waveform]
| BOUT_2MA_12
R_fixture =   1000
C_fixture =   0
L_fixture =   0
V_fixture =   1.2
V_fixture_min = 1.1
V_fixture_max = 1.3
|   Time   V(typ)   V(min)   V(max)
0s        1.2V       1.1V       1.3V
1.32ns    1.2V       1.1V       1.287V
1.775ns   1.2V       1.1V       179mV
2.27ns    1.2V       1.1V       34.77mV
3.78ns    1.186V     1.1V       31.99mV
4.645ns   189.8mV    1.1V       31.71mV
5.755ns   58.65mV    1.1V       31.57mV
10.09ns   56.4mV     1.089V     31.47mV
14.14ns   56.17mV    103.6mV    31.47mV
237.5ns   56.15mV    100.4mV    31.46mV
[Rising Waveform]
| BOUT_2MA_12
R_fixture =   1000
C_fixture =   0
L_fixture =   0
V_fixture =   1.2
V_fixture_min = 1.1
V_fixture_max = 1.3
|   Time   V(typ)   V(min)   V(max)
0s        56.15mV    100.4mV    31.46mV
710ps     56.24mV    100.4mV    61.66mV
1.2ns     55.68mV    100.4mV    1.166V
1.815ns   53.51mV    100.4mV    1.298V
2.555ns   130.8mV    100.5mV    1.299V
3.41ns    1.111V     99.55mV    1.3V
4.51ns    1.198V     97.02mV    1.3V
6.46ns    1.2V       142.5mV    1.3V
10.03ns   1.2V       1.097V     1.3V
237.5ns   1.2V       1.1V       1.3V
[Falling Waveform]
| BOUT_2MA_12
R_fixture =   1000
C_fixture =   0
L_fixture =   0
V_fixture =   0
V_fixture_min = 0
V_fixture_max = 0
|   Time   V(typ)   V(min)   V(max)
0s        1.128V     980.8mV    1.257V
1.315ns   1.128V     980.8mV    1.233V
1.76ns    1.128V     980.9mV    128.8mV
2.25ns    1.129V     980.8mV    2.97mV
3.755ns   1.091V     980.8mV    392.3uV
4.545ns   129.8mV    980.6mV    211.3uV
5.52ns    1.546mV    981.8mV    105.6uV
9.81ns    211.3uV    935.4mV    6.639uV
13.24ns   27.1uV     2.013mV    776.1nV
237.5ns   7.541nV    47.75nV    4.866nV
